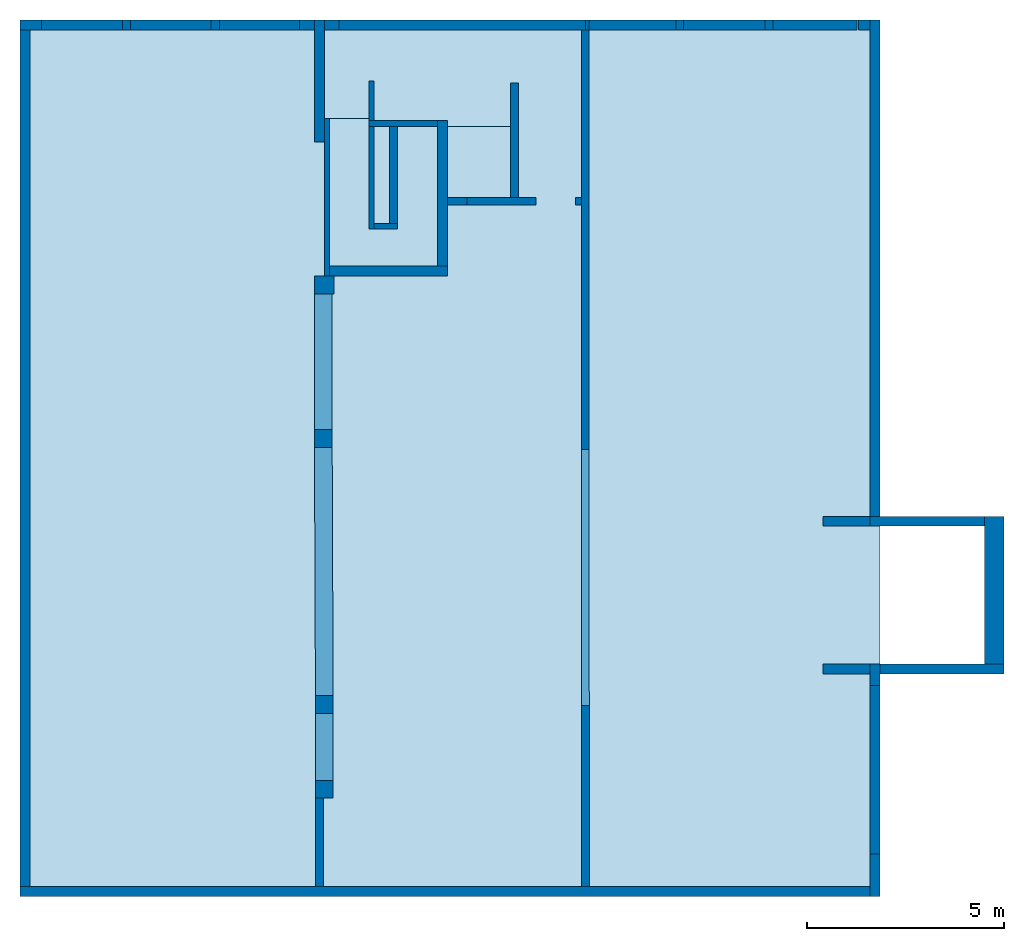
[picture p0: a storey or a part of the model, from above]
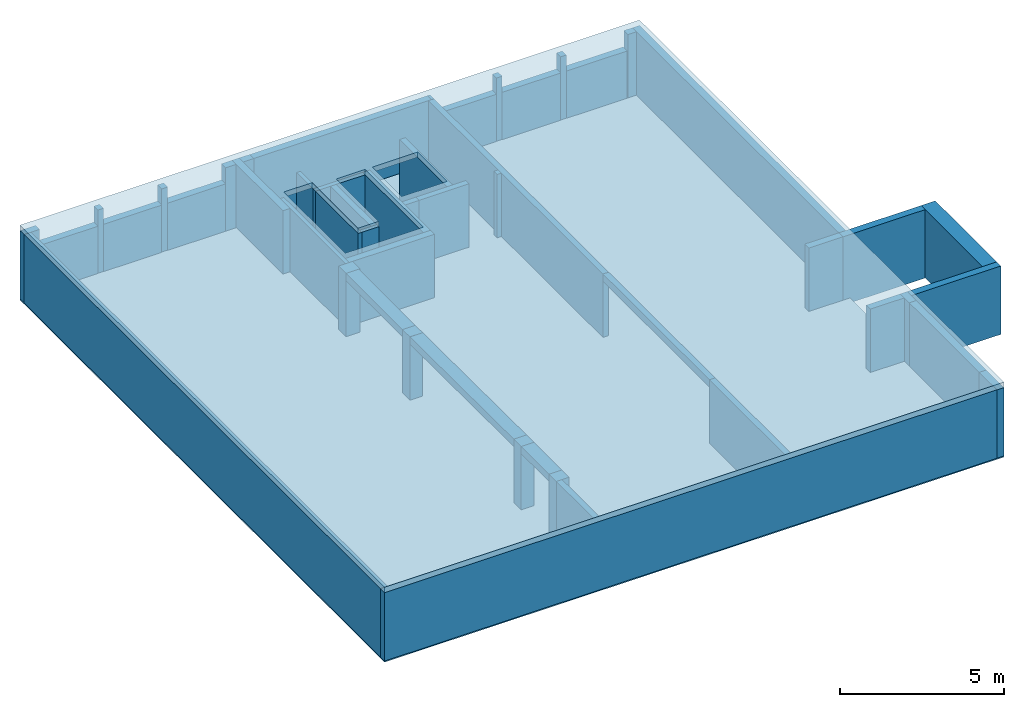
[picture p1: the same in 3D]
Properties of the parts of a building model (IFC2X3), part 1 of 2

# File
Description: ViewDefinition [CoordinationView_V2.0]
File name: C:\Users\steph\Desktop\Les Amaryllis complet pour Pcmo.ifc
Time: 2018-03-06T16:20:58
Author: Stéphane Hédouin
Organization: Nemetschek AG, Konrad-Zuse-Platz 1, 81829 Munich / Germany
Written by: EDMsix Version 2.0100.09 Sep 7 2016
Made in: Allplan 2018.0 16.11.2017 - 17:54:46

# IfcBuildingStorey (9)
In: Bâtiment
Name | Elevation (mm)
Sous-sol | -820
Rez-de-chaussée | 1760
1. Etage supérieur | 5290
2. Etage supérieur | 8450
3. Etage supérieur | 11610
4. Etage supérieur | 14770
5. Etage supérieur | 17930
6. Etage supérieur | 21090
7. Etage supérieur | 24250

# IfcBeam (24)
Material: <Unnamed Material>
Allplan Attributes - Catégorie de transformation: Nouvelle construction; Unité: m³
Name | In | Id_élt_Allmétré | NOI_UUID
<Unnamed Element> | Sous-sol | 0016S-p0000000009 | 486eb78d-af97-4655-ac4d-8411c6632bff--9
<Unnamed Element> | Sous-sol | 0016S-p0000000042 | 486eb78d-af97-4655-ac4d-8411c6632bff--42
<Unnamed Element> | Sous-sol | 0016S-p0000000049 | 486eb78d-af97-4655-ac4d-8411c6632bff--49
<Unnamed Element> | Sous-sol | 0016S-p0000000056 | 486eb78d-af97-4655-ac4d-8411c6632bff--56
<Unnamed Element> | Rez-de-chaussée | 0021S-p0000000030 | c5724ceb-6a8d-472c-a120-23266ca61e00--30
<Unnamed Element> | Rez-de-chaussée | 0021S-p0000000070 | c5724ceb-6a8d-472c-a120-23266ca61e00--70
<Unnamed Element> | Rez-de-chaussée | 0021S-p0000000063 | c5724ceb-6a8d-472c-a120-23266ca61e00--63
<Unnamed Element> | Rez-de-chaussée | 0021S-p0000000087 | c5724ceb-6a8d-472c-a120-23266ca61e00--87
<Unnamed Element> | Rez-de-chaussée | 0026S-p0000000118 | 649dd6d8-949c-4e9c-8996-63496c3fb143--118
<Unnamed Element> | Rez-de-chaussée | 0026S-p0000000126 | 649dd6d8-949c-4e9c-8996-63496c3fb143--126
<Unnamed Element> | Rez-de-chaussée | 0026S-p0000000246 | 649dd6d8-949c-4e9c-8996-63496c3fb143--246
<Unnamed Element> | 1. Etage supérieur | 0036S-p0000000018 | 9f9f1d74-6787-4617-af09-cd7453f099d3--18
<Unnamed Element> | 1. Etage supérieur | 0036S-p0000000057 | 9f9f1d74-6787-4617-af09-cd7453f099d3--57
<Unnamed Element> | 2. Etage supérieur | 0045S-p0000000002 | bfc77528-25da-4b58-ab56-61afc3e5380b--2
<Unnamed Element> | 2. Etage supérieur | 0045S-p0000000018 | bfc77528-25da-4b58-ab56-61afc3e5380b--18
<Unnamed Element> | 3. Etage supérieur | 0055S-p0000000017 | d36cbc1e-5176-4e0f-bb4e-4c807371ef2f--17
<Unnamed Element> | 3. Etage supérieur | 0055S-p0000000029 | d36cbc1e-5176-4e0f-bb4e-4c807371ef2f--29
<Unnamed Element> | 4. Etage supérieur | 0065S-p0000000069 | abeea69c-95b9-4fff-9f77-7789fcc0d115--69
<Unnamed Element> | 4. Etage supérieur | 0065S-p0000000017 | abeea69c-95b9-4fff-9f77-7789fcc0d115--17
<Unnamed Element> | 5. Etage supérieur | 0074S-p0000000016 | 6cb43bc7-a598-477d-aef1-ae12541f4cc3--16
<Unnamed Element> | 6. Etage supérieur | 0084S-p0000000007 | f4a9a238-371e-4109-9c43-8067f733ca4d--7
<Unnamed Element> | 6. Etage supérieur | 0084S-p0000000014 | f4a9a238-371e-4109-9c43-8067f733ca4d--14
<Unnamed Element> | 6. Etage supérieur | 0084S-p0000000070 | f4a9a238-371e-4109-9c43-8067f733ca4d--70
<Unnamed Element> | 6. Etage supérieur | 0084S-p0000000077 | f4a9a238-371e-4109-9c43-8067f733ca4d--77

# IfcColumn (21)
Material: <Unnamed Material>
Allplan Attributes - Catégorie de transformation: Nouvelle construction; Unité: m
Name | In | Id_élt_Allmétré | NOI_UUID
<Unnamed Element> | Sous-sol | 0013Pot0000000101 | f5a8dc2b-c76c-4dda-bb0b-31f6e3ff0e0c--101
<Unnamed Element> | Sous-sol | 0013Pot0000000109 | f5a8dc2b-c76c-4dda-bb0b-31f6e3ff0e0c--109
<Unnamed Element> | Sous-sol | 0013Pot0000000036 | f5a8dc2b-c76c-4dda-bb0b-31f6e3ff0e0c--36
<Unnamed Element> | Sous-sol | 0013Pot0000000044 | f5a8dc2b-c76c-4dda-bb0b-31f6e3ff0e0c--44
<Unnamed Element> | Sous-sol | 0013Pot0000000169 | f5a8dc2b-c76c-4dda-bb0b-31f6e3ff0e0c--169
<Unnamed Element> | Sous-sol | 0013Pot0000000177 | f5a8dc2b-c76c-4dda-bb0b-31f6e3ff0e0c--177
<Unnamed Element> | Sous-sol | 0013Pot0000000463 | f5a8dc2b-c76c-4dda-bb0b-31f6e3ff0e0c--463
<Unnamed Element> | Sous-sol | 0013Pot0000000455 | f5a8dc2b-c76c-4dda-bb0b-31f6e3ff0e0c--455
<Unnamed Element> | Rez-de-chaussée | 0022Pot0000000309 | 0e2b27f9-10d3-4386-be4d-cd432914257b--309
<Unnamed Element> | Rez-de-chaussée | 0023Pot0000000124 | 0033ac79-3276-4870-90e0-ad52ccc84e25--124
<Unnamed Element> | Rez-de-chaussée | 0023Pot0000000121 | 0033ac79-3276-4870-90e0-ad52ccc84e25--121
<Unnamed Element> | Rez-de-chaussée | 0023Pot0000000118 | 0033ac79-3276-4870-90e0-ad52ccc84e25--118
<Unnamed Element> | Rez-de-chaussée | 0023Pot0000000115 | 0033ac79-3276-4870-90e0-ad52ccc84e25--115
<Unnamed Element> | Rez-de-chaussée | 0023Pot0000000112 | 0033ac79-3276-4870-90e0-ad52ccc84e25--112
<Unnamed Element> | Rez-de-chaussée | 0023Pot0000000109 | 0033ac79-3276-4870-90e0-ad52ccc84e25--109
<Unnamed Element> | Rez-de-chaussée | 0023Pot0000000106 | 0033ac79-3276-4870-90e0-ad52ccc84e25--106
<Unnamed Element> | Rez-de-chaussée | 0023Pot0000000103 | 0033ac79-3276-4870-90e0-ad52ccc84e25--103
<Unnamed Element> | Rez-de-chaussée | 0023Pot0000000100 | 0033ac79-3276-4870-90e0-ad52ccc84e25--100
<Unnamed Element> | Rez-de-chaussée | 0023Pot0000000097 | 0033ac79-3276-4870-90e0-ad52ccc84e25--97
<Unnamed Element> | Rez-de-chaussée | 0023Pot0000000091 | 0033ac79-3276-4870-90e0-ad52ccc84e25--91
<Unnamed Element> | Rez-de-chaussée | 0023Pot0000000094 | 0033ac79-3276-4870-90e0-ad52ccc84e25--94

# IfcOpeningElement: Opening (179)
Allplan Attributes - Object Layer Attributes #1, Catégorie de transformation: Nouvelle construction; Object Layer Attributes #1, Unité: m²
Name | In | Object Layer Attributes #1, Id_élt_Allmétré | Object Layer Attributes #1, NOI_UUID | Object Layer Attributes #1, Métier
Trémie dans dalle | Sous-sol | 0014TrD0000000013 | 20334fe0-4999-4aaf-8585-79f5e6d3d731--13
Trémie dans dalle | Sous-sol | 0014TrD0000000025 | 20334fe0-4999-4aaf-8585-79f5e6d3d731--25
Trémie dans dalle | Rez-de-chaussée | 0027TrD0000000023 | d315fca0-df44-48a9-a052-42f8cd2f5afa--23
Trémie dans dalle | Rez-de-chaussée | 0027TrD0000000180 | d315fca0-df44-48a9-a052-42f8cd2f5afa--180
Baie de porte | 1. Etage supérieur | 0032Por0000004570 | 6a1e8f65-a2b8-4168-b325-3206246c0164--4570 | Béton et béton armé
Baie de fenêtre | 1. Etage supérieur | 0032Fen0000004470 | 6a1e8f65-a2b8-4168-b325-3206246c0164--4470 | Béton et béton armé
Baie de fenêtre | 1. Etage supérieur | 0032Fen0000004484 | 6a1e8f65-a2b8-4168-b325-3206246c0164--4484 | Béton et béton armé
Baie de fenêtre | 1. Etage supérieur | 0032Fen0000004417 | 6a1e8f65-a2b8-4168-b325-3206246c0164--4417 | Béton et béton armé
Baie de fenêtre | 1. Etage supérieur | 0032Fen0000004432 | 6a1e8f65-a2b8-4168-b325-3206246c0164--4432 | Béton et béton armé
Baie de fenêtre | 1. Etage supérieur | 0032Fen0000004445 | 6a1e8f65-a2b8-4168-b325-3206246c0164--4445 | Béton et béton armé
Baie de fenêtre | 1. Etage supérieur | 0032Fen0000004458 | 6a1e8f65-a2b8-4168-b325-3206246c0164--4458 | Béton et béton armé
Baie de fenêtre | 1. Etage supérieur | 0032Fen0000004272 | 6a1e8f65-a2b8-4168-b325-3206246c0164--4272 | Béton et béton armé
Baie de fenêtre | 1. Etage supérieur | 0032Fen0000004288 | 6a1e8f65-a2b8-4168-b325-3206246c0164--4288 | Béton et béton armé
Baie de fenêtre | 1. Etage supérieur | 0032Fen0000004332 | 6a1e8f65-a2b8-4168-b325-3206246c0164--4332 | Béton et béton armé
Baie de porte | 1. Etage supérieur | 0032Por0000004666 | 6a1e8f65-a2b8-4168-b325-3206246c0164--4666 | Béton et béton armé
Baie de fenêtre | 1. Etage supérieur | 0032Fen0000004525 | 6a1e8f65-a2b8-4168-b325-3206246c0164--4525 | Béton et béton armé
Baie de fenêtre | 1. Etage supérieur | 0032Fen0000004583 | 6a1e8f65-a2b8-4168-b325-3206246c0164--4583 | Béton et béton armé
Baie de fenêtre | 1. Etage supérieur | 0032Fen0000004593 | 6a1e8f65-a2b8-4168-b325-3206246c0164--4593 | Béton et béton armé
Baie de fenêtre | 1. Etage supérieur | 0032Fen0000004535 | 6a1e8f65-a2b8-4168-b325-3206246c0164--4535 | Béton et béton armé
Baie de fenêtre | 1. Etage supérieur | 0032Fen0000003807 | 6a1e8f65-a2b8-4168-b325-3206246c0164--3807 | Béton et béton armé
Baie de fenêtre | 1. Etage supérieur | 0032Fen0000004259 | 6a1e8f65-a2b8-4168-b325-3206246c0164--4259 | Béton et béton armé
Baie de fenêtre | 1. Etage supérieur | 0032Fen0000004400 | 6a1e8f65-a2b8-4168-b325-3206246c0164--4400 | Béton et béton armé
Baie de fenêtre | 1. Etage supérieur | 0032Fen0000004386 | 6a1e8f65-a2b8-4168-b325-3206246c0164--4386 | Béton et béton armé
Baie de fenêtre | 1. Etage supérieur | 0032Fen0000004360 | 6a1e8f65-a2b8-4168-b325-3206246c0164--4360 | Béton et béton armé
Baie de fenêtre | 1. Etage supérieur | 0032Fen0000004346 | 6a1e8f65-a2b8-4168-b325-3206246c0164--4346 | Béton et béton armé
Trémie dans dalle | 1. Etage supérieur | 0034TrD0000000056 | ebf78192-9004-4931-9720-7fce9c6b5ec9--56
Trémie dans dalle | 1. Etage supérieur | 0034TrD0000000061 | ebf78192-9004-4931-9720-7fce9c6b5ec9--61
Baie de fenêtre | 2. Etage supérieur | 0042Fen0000000908 | 90a796d3-f0ad-4bd1-a568-830c8568f6ce--908 | Menuiserie
Baie de fenêtre | 2. Etage supérieur | 0042Fen0000000878 | 90a796d3-f0ad-4bd1-a568-830c8568f6ce--878 | Menuiserie
Baie de fenêtre | 2. Etage supérieur | 0042Fen0000000868 | 90a796d3-f0ad-4bd1-a568-830c8568f6ce--868 | Menuiserie
Baie de fenêtre | 2. Etage supérieur | 0042Fen0000000784 | 90a796d3-f0ad-4bd1-a568-830c8568f6ce--784 | Menuiserie
Baie de fenêtre | 2. Etage supérieur | 0042Fen0000000794 | 90a796d3-f0ad-4bd1-a568-830c8568f6ce--794 | Menuiserie
Baie de fenêtre | 2. Etage supérieur | 0042Fen0000000772 | 90a796d3-f0ad-4bd1-a568-830c8568f6ce--772 | Menuiserie
Baie de fenêtre | 2. Etage supérieur | 0042Fen0000000748 | 90a796d3-f0ad-4bd1-a568-830c8568f6ce--748 | Menuiserie
Baie de fenêtre | 2. Etage supérieur | 0042Fen0000000760 | 90a796d3-f0ad-4bd1-a568-830c8568f6ce--760 | Menuiserie
Baie de fenêtre | 2. Etage supérieur | 0042Fen0000000706 | 90a796d3-f0ad-4bd1-a568-830c8568f6ce--706 | Menuiserie
Porte-fenêtre | 2. Etage supérieur | 0042PoF0000001016 | 90a796d3-f0ad-4bd1-a568-830c8568f6ce--1016 | Menuiserie
Baie de fenêtre | 2. Etage supérieur | 0042Fen0000000918 | 90a796d3-f0ad-4bd1-a568-830c8568f6ce--918 | Menuiserie
Baie de fenêtre | 2. Etage supérieur | 0042Fen0000000858 | 90a796d3-f0ad-4bd1-a568-830c8568f6ce--858 | Menuiserie
Baie de fenêtre | 2. Etage supérieur | 0042Fen0000000848 | 90a796d3-f0ad-4bd1-a568-830c8568f6ce--848 | Menuiserie
Baie de fenêtre | 2. Etage supérieur | 0042Fen0000000898 | 90a796d3-f0ad-4bd1-a568-830c8568f6ce--898 | Menuiserie
Baie de fenêtre | 2. Etage supérieur | 0042Fen0000000928 | 90a796d3-f0ad-4bd1-a568-830c8568f6ce--928 | Menuiserie
Baie de fenêtre | 2. Etage supérieur | 0042Fen0000000938 | 90a796d3-f0ad-4bd1-a568-830c8568f6ce--938 | Menuiserie
Baie de fenêtre | 2. Etage supérieur | 0042Fen0000000888 | 90a796d3-f0ad-4bd1-a568-830c8568f6ce--888 | Menuiserie
Baie de fenêtre | 2. Etage supérieur | 0042Fen0000000838 | 90a796d3-f0ad-4bd1-a568-830c8568f6ce--838 | Menuiserie
Baie de fenêtre | 2. Etage supérieur | 0042Fen0000000828 | 90a796d3-f0ad-4bd1-a568-830c8568f6ce--828 | Menuiserie
Baie de fenêtre | 2. Etage supérieur | 0042Fen0000000818 | 90a796d3-f0ad-4bd1-a568-830c8568f6ce--818 | Menuiserie
Baie de fenêtre | 2. Etage supérieur | 0042Fen0000000808 | 90a796d3-f0ad-4bd1-a568-830c8568f6ce--808 | Menuiserie
Porte-fenêtre | 2. Etage supérieur | 0042PoF0000002495 | 90a796d3-f0ad-4bd1-a568-830c8568f6ce--2495 | Menuiserie
Baie de fenêtre | 2. Etage supérieur | 0042Fen0000001087 | 90a796d3-f0ad-4bd1-a568-830c8568f6ce--1087 | Menuiserie
Baie de fenêtre | 2. Etage supérieur | 0042Fen0000001131 | 90a796d3-f0ad-4bd1-a568-830c8568f6ce--1131 | Menuiserie
Baie de fenêtre | 2. Etage supérieur | 0042Fen0000001121 | 90a796d3-f0ad-4bd1-a568-830c8568f6ce--1121 | Menuiserie
Baie de fenêtre | 2. Etage supérieur | 0042Fen0000002478 | 90a796d3-f0ad-4bd1-a568-830c8568f6ce--2478 | Menuiserie
Trémie dans dalle | 2. Etage supérieur | 0043TrD0000000213 | 678bda4c-4d8f-426f-a236-f3a8bbcb65b3--213
Trémie dans dalle | 2. Etage supérieur | 0043TrD0000000220 | 678bda4c-4d8f-426f-a236-f3a8bbcb65b3--220
Trémie dans dalle | 2. Etage supérieur | 0043TrD0000000225 | 678bda4c-4d8f-426f-a236-f3a8bbcb65b3--225
Baie de fenêtre | 3. Etage supérieur | 0052Fen0000000426 | 435ab560-3884-4131-b1cc-7aba0e0d0a30--426 | Menuiserie
Baie de fenêtre | 3. Etage supérieur | 0052Fen0000000436 | 435ab560-3884-4131-b1cc-7aba0e0d0a30--436 | Menuiserie
Porte-fenêtre | 3. Etage supérieur | 0052PoF0000000588 | 435ab560-3884-4131-b1cc-7aba0e0d0a30--588 | Menuiserie
Baie de fenêtre | 3. Etage supérieur | 0052Fen0000000710 | 435ab560-3884-4131-b1cc-7aba0e0d0a30--710 | Menuiserie
Baie de fenêtre | 3. Etage supérieur | 0052Fen0000000690 | 435ab560-3884-4131-b1cc-7aba0e0d0a30--690 | Menuiserie
Baie de fenêtre | 3. Etage supérieur | 0052Fen0000000700 | 435ab560-3884-4131-b1cc-7aba0e0d0a30--700 | Menuiserie
Baie de fenêtre | 3. Etage supérieur | 0052Fen0000000720 | 435ab560-3884-4131-b1cc-7aba0e0d0a30--720 | Menuiserie
Porte-fenêtre | 3. Etage supérieur | 0052PoF0000000577 | 435ab560-3884-4131-b1cc-7aba0e0d0a30--577 | Menuiserie
Baie de fenêtre | 3. Etage supérieur | 0052Fen0000000416 | 435ab560-3884-4131-b1cc-7aba0e0d0a30--416 | Menuiserie
Baie de fenêtre | 3. Etage supérieur | 0052Fen0000000372 | 435ab560-3884-4131-b1cc-7aba0e0d0a30--372 | Menuiserie
Baie de fenêtre | 3. Etage supérieur | 0052Fen0000000402 | 435ab560-3884-4131-b1cc-7aba0e0d0a30--402 | Menuiserie
Baie de fenêtre | 3. Etage supérieur | 0052Fen0000000526 | 435ab560-3884-4131-b1cc-7aba0e0d0a30--526 | Menuiserie
Baie de fenêtre | 3. Etage supérieur | 0052Fen0000000516 | 435ab560-3884-4131-b1cc-7aba0e0d0a30--516 | Menuiserie
Baie de fenêtre | 3. Etage supérieur | 0052Fen0000000506 | 435ab560-3884-4131-b1cc-7aba0e0d0a30--506 | Menuiserie
Baie de fenêtre | 3. Etage supérieur | 0052Fen0000000496 | 435ab560-3884-4131-b1cc-7aba0e0d0a30--496 | Menuiserie
Baie de fenêtre | 3. Etage supérieur | 0052Fen0000000392 | 435ab560-3884-4131-b1cc-7aba0e0d0a30--392 | Menuiserie
Baie de fenêtre | 3. Etage supérieur | 0052Fen0000000486 | 435ab560-3884-4131-b1cc-7aba0e0d0a30--486 | Menuiserie
Baie de fenêtre | 3. Etage supérieur | 0052Fen0000000476 | 435ab560-3884-4131-b1cc-7aba0e0d0a30--476 | Menuiserie
Baie de fenêtre | 3. Etage supérieur | 0052Fen0000000466 | 435ab560-3884-4131-b1cc-7aba0e0d0a30--466 | Menuiserie
Baie de fenêtre | 3. Etage supérieur | 0052Fen0000000362 | 435ab560-3884-4131-b1cc-7aba0e0d0a30--362 | Menuiserie
Baie de fenêtre | 3. Etage supérieur | 0052Fen0000000352 | 435ab560-3884-4131-b1cc-7aba0e0d0a30--352 | Menuiserie
Baie de fenêtre | 3. Etage supérieur | 0052Fen0000000456 | 435ab560-3884-4131-b1cc-7aba0e0d0a30--456 | Menuiserie
Baie de fenêtre | 3. Etage supérieur | 0052Fen0000000446 | 435ab560-3884-4131-b1cc-7aba0e0d0a30--446 | Menuiserie
Baie de fenêtre | 3. Etage supérieur | 0052Fen0000000382 | 435ab560-3884-4131-b1cc-7aba0e0d0a30--382 | Menuiserie
Baie de fenêtre | 3. Etage supérieur | 0052Fen0000000340 | 435ab560-3884-4131-b1cc-7aba0e0d0a30--340 | Menuiserie
Porte-fenêtre | 3. Etage supérieur | 0052PoF0000000622 | 435ab560-3884-4131-b1cc-7aba0e0d0a30--622 | Menuiserie
Porte-fenêtre | 3. Etage supérieur | 0052PoF0000000633 | 435ab560-3884-4131-b1cc-7aba0e0d0a30--633 | Menuiserie
Porte-fenêtre | 3. Etage supérieur | 0052PoF0000000611 | 435ab560-3884-4131-b1cc-7aba0e0d0a30--611 | Menuiserie
Porte-fenêtre | 3. Etage supérieur | 0052PoF0000000679 | 435ab560-3884-4131-b1cc-7aba0e0d0a30--679 | Menuiserie
Porte-fenêtre | 3. Etage supérieur | 0052PoF0000000668 | 435ab560-3884-4131-b1cc-7aba0e0d0a30--668 | Menuiserie
Trémie dans dalle | 3. Etage supérieur | 0053TrD0000000277 | 48b77cce-8fe0-481c-bd89-f567615fd88a--277
Trémie dans dalle | 3. Etage supérieur | 0053TrD0000000282 | 48b77cce-8fe0-481c-bd89-f567615fd88a--282
Trémie dans dalle | 3. Etage supérieur | 0053TrD0000000287 | 48b77cce-8fe0-481c-bd89-f567615fd88a--287
Porte-fenêtre | 4. Etage supérieur | 0062PoF0000001083 | 347db150-1122-4b3f-bc21-631404b16890--1083 | Menuiserie
Porte-fenêtre | 4. Etage supérieur | 0062PoF0000000532 | 347db150-1122-4b3f-bc21-631404b16890--532 | Menuiserie
Porte-fenêtre | 4. Etage supérieur | 0062PoF0000001070 | 347db150-1122-4b3f-bc21-631404b16890--1070 | Menuiserie
Porte-fenêtre | 4. Etage supérieur | 0062PoF0000000486 | 347db150-1122-4b3f-bc21-631404b16890--486 | Menuiserie
Porte-fenêtre | 4. Etage supérieur | 0062PoF0000000543 | 347db150-1122-4b3f-bc21-631404b16890--543 | Menuiserie
Baie de fenêtre | 4. Etage supérieur | 0062Fen0000001057 | 347db150-1122-4b3f-bc21-631404b16890--1057 | Menuiserie
Porte-fenêtre | 4. Etage supérieur | 0062PoF0000000470 | 347db150-1122-4b3f-bc21-631404b16890--470 | Menuiserie
Baie de fenêtre | 4. Etage supérieur | 0062Fen0000000554 | 347db150-1122-4b3f-bc21-631404b16890--554 | Menuiserie
Baie de fenêtre | 4. Etage supérieur | 0062Fen0000000560 | 347db150-1122-4b3f-bc21-631404b16890--560 | Menuiserie
Baie de fenêtre | 4. Etage supérieur | 0062Fen0000000572 | 347db150-1122-4b3f-bc21-631404b16890--572 | Menuiserie
Baie de fenêtre | 4. Etage supérieur | 0062Fen0000000566 | 347db150-1122-4b3f-bc21-631404b16890--566 | Menuiserie
Porte-fenêtre | 4. Etage supérieur | 0062PoF0000000459 | 347db150-1122-4b3f-bc21-631404b16890--459 | Menuiserie
Baie de fenêtre | 4. Etage supérieur | 0062Fen0000001041 | 347db150-1122-4b3f-bc21-631404b16890--1041 | Menuiserie
Baie de fenêtre | 4. Etage supérieur | 0062Fen0000001029 | 347db150-1122-4b3f-bc21-631404b16890--1029 | Menuiserie
Baie de fenêtre | 4. Etage supérieur | 0062Fen0000001017 | 347db150-1122-4b3f-bc21-631404b16890--1017 | Menuiserie
Baie de fenêtre | 4. Etage supérieur | 0062Fen0000000995 | 347db150-1122-4b3f-bc21-631404b16890--995 | Menuiserie
Baie de fenêtre | 4. Etage supérieur | 0062Fen0000000983 | 347db150-1122-4b3f-bc21-631404b16890--983 | Menuiserie
Baie de fenêtre | 4. Etage supérieur | 0062Fen0000000971 | 347db150-1122-4b3f-bc21-631404b16890--971 | Menuiserie
Baie de fenêtre | 4. Etage supérieur | 0062Fen0000000959 | 347db150-1122-4b3f-bc21-631404b16890--959 | Menuiserie
Baie de fenêtre | 4. Etage supérieur | 0062Fen0000000947 | 347db150-1122-4b3f-bc21-631404b16890--947 | Menuiserie
Baie de fenêtre | 4. Etage supérieur | 0062Fen0000000925 | 347db150-1122-4b3f-bc21-631404b16890--925 | Menuiserie
Baie de fenêtre | 4. Etage supérieur | 0062Fen0000000913 | 347db150-1122-4b3f-bc21-631404b16890--913 | Menuiserie
Baie de fenêtre | 4. Etage supérieur | 0062Fen0000000901 | 347db150-1122-4b3f-bc21-631404b16890--901 | Menuiserie
Baie de fenêtre | 4. Etage supérieur | 0062Fen0000000889 | 347db150-1122-4b3f-bc21-631404b16890--889 | Menuiserie
Baie de fenêtre | 4. Etage supérieur | 0062Fen0000000877 | 347db150-1122-4b3f-bc21-631404b16890--877 | Menuiserie
Porte-fenêtre | 4. Etage supérieur | 0062PoF0000000497 | 347db150-1122-4b3f-bc21-631404b16890--497 | Menuiserie
Porte-fenêtre | 4. Etage supérieur | 0062PoF0000000504 | 347db150-1122-4b3f-bc21-631404b16890--504 | Menuiserie
Baie de fenêtre | 4. Etage supérieur | 0062Fen0000000855 | 347db150-1122-4b3f-bc21-631404b16890--855 | Menuiserie
Baie de fenêtre | 4. Etage supérieur | 0062Fen0000000842 | 347db150-1122-4b3f-bc21-631404b16890--842 | Menuiserie
Baie de fenêtre | 4. Etage supérieur | 0062Fen0000000798 | 347db150-1122-4b3f-bc21-631404b16890--798 | Menuiserie
Trémie dans dalle | 4. Etage supérieur | 0063TrD0000000021 | 91ba3f86-ed78-430b-84a1-b3a13398379c--21
Trémie dans dalle | 4. Etage supérieur | 0063TrD0000000026 | 91ba3f86-ed78-430b-84a1-b3a13398379c--26
Trémie dans dalle | 4. Etage supérieur | 0063TrD0000000016 | 91ba3f86-ed78-430b-84a1-b3a13398379c--16
Porte-fenêtre | 5. Etage supérieur | 0071PoF0000001617 | ef38cf39-5122-4ad7-8e20-12f51fd6f56f--1617 | Menuiserie
Porte-fenêtre | 5. Etage supérieur | 0071PoF0000001629 | ef38cf39-5122-4ad7-8e20-12f51fd6f56f--1629 | Menuiserie
Baie de fenêtre | 5. Etage supérieur | 0071Fen0000001931 | ef38cf39-5122-4ad7-8e20-12f51fd6f56f--1931 | Menuiserie
Baie de fenêtre | 5. Etage supérieur | 0071Fen0000001943 | ef38cf39-5122-4ad7-8e20-12f51fd6f56f--1943 | Menuiserie
Baie de fenêtre | 5. Etage supérieur | 0071Fen0000002153 | ef38cf39-5122-4ad7-8e20-12f51fd6f56f--2153 | Menuiserie
Baie de fenêtre | 5. Etage supérieur | 0071Fen0000002141 | ef38cf39-5122-4ad7-8e20-12f51fd6f56f--2141 | Menuiserie
Porte-fenêtre | 5. Etage supérieur | 0071PoF0000001467 | ef38cf39-5122-4ad7-8e20-12f51fd6f56f--1467 | Menuiserie
Baie de fenêtre | 5. Etage supérieur | 0071Fen0000001504 | ef38cf39-5122-4ad7-8e20-12f51fd6f56f--1504 | Menuiserie
Baie de fenêtre | 5. Etage supérieur | 0071Fen0000001500 | ef38cf39-5122-4ad7-8e20-12f51fd6f56f--1500 | Menuiserie
Baie de fenêtre | 5. Etage supérieur | 0071Fen0000001498 | ef38cf39-5122-4ad7-8e20-12f51fd6f56f--1498 | Menuiserie
Baie de fenêtre | 5. Etage supérieur | 0071Fen0000001502 | ef38cf39-5122-4ad7-8e20-12f51fd6f56f--1502 | Menuiserie
Porte-fenêtre | 5. Etage supérieur | 0071PoF0000001533 | ef38cf39-5122-4ad7-8e20-12f51fd6f56f--1533 | Menuiserie
Baie de fenêtre | 5. Etage supérieur | 0071Fen0000002117 | ef38cf39-5122-4ad7-8e20-12f51fd6f56f--2117 | Menuiserie
Baie de fenêtre | 5. Etage supérieur | 0071Fen0000002129 | ef38cf39-5122-4ad7-8e20-12f51fd6f56f--2129 | Menuiserie
Baie de fenêtre | 5. Etage supérieur | 0071Fen0000002079 | ef38cf39-5122-4ad7-8e20-12f51fd6f56f--2079 | Menuiserie
Baie de fenêtre | 5. Etage supérieur | 0071Fen0000002043 | ef38cf39-5122-4ad7-8e20-12f51fd6f56f--2043 | Menuiserie
Baie de fenêtre | 5. Etage supérieur | 0071Fen0000002055 | ef38cf39-5122-4ad7-8e20-12f51fd6f56f--2055 | Menuiserie
Baie de fenêtre | 5. Etage supérieur | 0071Fen0000002067 | ef38cf39-5122-4ad7-8e20-12f51fd6f56f--2067 | Menuiserie
Baie de fenêtre | 5. Etage supérieur | 0071Fen0000002089 | ef38cf39-5122-4ad7-8e20-12f51fd6f56f--2089 | Menuiserie
Baie de fenêtre | 5. Etage supérieur | 0071Fen0000002105 | ef38cf39-5122-4ad7-8e20-12f51fd6f56f--2105 | Menuiserie
Porte-fenêtre | 5. Etage supérieur | 0071PoF0000001555 | ef38cf39-5122-4ad7-8e20-12f51fd6f56f--1555 | Menuiserie
Porte-fenêtre | 5. Etage supérieur | 0071PoF0000001568 | ef38cf39-5122-4ad7-8e20-12f51fd6f56f--1568 | Menuiserie
Porte-fenêtre | 5. Etage supérieur | 0071PoF0000001566 | ef38cf39-5122-4ad7-8e20-12f51fd6f56f--1566 | Menuiserie
Porte-fenêtre | 5. Etage supérieur | 0071PoF0000001581 | ef38cf39-5122-4ad7-8e20-12f51fd6f56f--1581 | Menuiserie
Baie de fenêtre | 5. Etage supérieur | 0071Fen0000002031 | ef38cf39-5122-4ad7-8e20-12f51fd6f56f--2031 | Menuiserie
Baie de fenêtre | 5. Etage supérieur | 0071Fen0000002019 | ef38cf39-5122-4ad7-8e20-12f51fd6f56f--2019 | Menuiserie
Baie de fenêtre | 5. Etage supérieur | 0071Fen0000002007 | ef38cf39-5122-4ad7-8e20-12f51fd6f56f--2007 | Menuiserie
Baie de fenêtre | 5. Etage supérieur | 0071Fen0000001995 | ef38cf39-5122-4ad7-8e20-12f51fd6f56f--1995 | Menuiserie
Baie de fenêtre | 5. Etage supérieur | 0071Fen0000001983 | ef38cf39-5122-4ad7-8e20-12f51fd6f56f--1983 | Menuiserie
Trémie dans dalle | 5. Etage supérieur | 0072TrD0000000020 | dce49d39-f4d7-4afb-90a5-12dc6dbe4ed2--20
Trémie dans dalle | 5. Etage supérieur | 0072TrD0000000025 | dce49d39-f4d7-4afb-90a5-12dc6dbe4ed2--25
Baie de fenêtre | 6. Etage supérieur | 0082Fen0000000678 | 5473e48a-e790-4312-ac25-e6982c2e7877--678 | Béton et béton armé
Baie de fenêtre | 6. Etage supérieur | 0082Fen0000000692 | 5473e48a-e790-4312-ac25-e6982c2e7877--692 | Béton et béton armé
Baie de fenêtre | 6. Etage supérieur | 0082Fen0000000704 | 5473e48a-e790-4312-ac25-e6982c2e7877--704 | Béton et béton armé
Baie de fenêtre | 6. Etage supérieur | 0082Fen0000000728 | 5473e48a-e790-4312-ac25-e6982c2e7877--728 | Béton et béton armé
Baie de fenêtre | 6. Etage supérieur | 0082Fen0000000750 | 5473e48a-e790-4312-ac25-e6982c2e7877--750 | Béton et béton armé
Baie de fenêtre | 6. Etage supérieur | 0082Fen0000000774 | 5473e48a-e790-4312-ac25-e6982c2e7877--774 | Béton et béton armé
Baie de fenêtre | 6. Etage supérieur | 0082Fen0000000786 | 5473e48a-e790-4312-ac25-e6982c2e7877--786 | Béton et béton armé
Baie de fenêtre | 6. Etage supérieur | 0082Fen0000000798 | 5473e48a-e790-4312-ac25-e6982c2e7877--798 | Béton et béton armé
Baie de fenêtre | 6. Etage supérieur | 0082Fen0000000810 | 5473e48a-e790-4312-ac25-e6982c2e7877--810 | Béton et béton armé
Baie de porte | 6. Etage supérieur | 0082Por0000001034 | 5473e48a-e790-4312-ac25-e6982c2e7877--1034 | Béton et béton armé
Baie de fenêtre | 6. Etage supérieur | 0082Fen0000000762 | 5473e48a-e790-4312-ac25-e6982c2e7877--762 | Béton et béton armé
Baie de fenêtre | 6. Etage supérieur | 0082Fen0000000557 | 5473e48a-e790-4312-ac25-e6982c2e7877--557 | Béton et béton armé
Baie de fenêtre | 6. Etage supérieur | 0082Fen0000000569 | 5473e48a-e790-4312-ac25-e6982c2e7877--569 | Béton et béton armé
Baie de fenêtre | 6. Etage supérieur | 0082Fen0000000581 | 5473e48a-e790-4312-ac25-e6982c2e7877--581 | Béton et béton armé
Baie de fenêtre | 6. Etage supérieur | 0082Fen0000000593 | 5473e48a-e790-4312-ac25-e6982c2e7877--593 | Béton et béton armé
Baie de fenêtre | 6. Etage supérieur | 0082Fen0000000605 | 5473e48a-e790-4312-ac25-e6982c2e7877--605 | Béton et béton armé
Porte-fenêtre | 6. Etage supérieur | 0082PoF0000000849 | 5473e48a-e790-4312-ac25-e6982c2e7877--849 | Béton et béton armé
Porte-fenêtre | 6. Etage supérieur | 0082PoF0000000881 | 5473e48a-e790-4312-ac25-e6982c2e7877--881 | Béton et béton armé
Baie de fenêtre | 6. Etage supérieur | 0082Fen0000000618 | 5473e48a-e790-4312-ac25-e6982c2e7877--618 | Béton et béton armé
Baie de fenêtre | 6. Etage supérieur | 0082Fen0000000630 | 5473e48a-e790-4312-ac25-e6982c2e7877--630 | Béton et béton armé
Baie de fenêtre | 6. Etage supérieur | 0082Fen0000000642 | 5473e48a-e790-4312-ac25-e6982c2e7877--642 | Béton et béton armé
Baie de fenêtre | 6. Etage supérieur | 0082Fen0000000654 | 5473e48a-e790-4312-ac25-e6982c2e7877--654 | Béton et béton armé
Baie de fenêtre | 6. Etage supérieur | 0082Fen0000000666 | 5473e48a-e790-4312-ac25-e6982c2e7877--666 | Béton et béton armé
Baie de porte | 6. Etage supérieur | 0082Por0000001022 | 5473e48a-e790-4312-ac25-e6982c2e7877--1022 | Béton et béton armé
Trémie dans dalle | 6. Etage supérieur | 0083TrD0000000021 | f7d33bd0-1ac0-43b7-ade3-e2a972c2ffc9--21
Trémie dans dalle | 6. Etage supérieur | 0083TrD0000000026 | f7d33bd0-1ac0-43b7-ade3-e2a972c2ffc9--26

# IfcSlab (10)
PredefinedType: FLOOR
Allplan Attributes - Catégorie de transformation: Nouvelle construction; Unité: m²
Name | In | Material | Id_élt_Allmétré | NOI_UUID
<Unnamed Element> | Sous-sol | <Unnamed Material> 200 mm | 0014Dal0000000002 | 20334fe0-4999-4aaf-8585-79f5e6d3d731--2
<Unnamed Element> | Sous-sol | <Unnamed Material> 230 mm | 0018Dal0000000020 | c1ec093b-a0e2-4153-afd5-b799a6e003fa--20
<Unnamed Element> | Rez-de-chaussée | <Unnamed Material> 230 mm | 0027Dal0000000020 | d315fca0-df44-48a9-a052-42f8cd2f5afa--20
<Unnamed Element> | 1. Etage supérieur | <Unnamed Material> 230 mm | 0034Dal0000000053 | ebf78192-9004-4931-9720-7fce9c6b5ec9--53
<Unnamed Element> | 2. Etage supérieur | <Unnamed Material> 230 mm | 0043Dal0000000004 | 678bda4c-4d8f-426f-a236-f3a8bbcb65b3--4
<Unnamed Element> | 3. Etage supérieur | <Unnamed Material> 230 mm | 0053Dal0000000002 | 48b77cce-8fe0-481c-bd89-f567615fd88a--2
<Unnamed Element> | 4. Etage supérieur | <Unnamed Material> 230 mm | 0063Dal0000000002 | 91ba3f86-ed78-430b-84a1-b3a13398379c--2
<Unnamed Element> | 5. Etage supérieur | <Unnamed Material> 230 mm | 0072Dal0000000004 | dce49d39-f4d7-4afb-90a5-12dc6dbe4ed2--4
<Unnamed Element> | 6. Etage supérieur | <Unnamed Material> 230 mm | 0083Dal0000000002 | f7d33bd0-1ac0-43b7-ade3-e2a972c2ffc9--2
<Unnamed Element> | 7. Etage supérieur | <Unnamed Material> 200 mm | 0094Dal0000000003 | 8a5cfb47-16d0-4201-be59-6f41295b1b2b--3

# IfcStair, <Unnamed Element>
In: Rez-de-chaussée
Material: Escalier semi-tournant
Pset_StairCommon - NumberOfRiser: 16; RiserHeight: 246.25 mm; TreadLength: 300.83 mm; NumberOfTreads: 16
Allplan Attributes - Id_élt_Allmétré: 0026Esc0000000029; Unité: Qt; Matériau: Escalier semi-tournant; NOI_UUID: 649dd6d8-949c-4e9c-8996-63496c3fb143--29

# IfcWallStandardCase (211)
Allplan Attributes - Unité: m³; Object Layer Attributes #1, Catégorie de transformation: Nouvelle construction; Object Layer Attributes #1, Unité: m²
Name | In | Material | Id_élt_Allmétré | NOI_UUID | Object Layer Attributes #1, Id_élt_Allmétré | Object Layer Attributes #1, Métier | Object Layer Attributes #1, NOI_UUID
<Unnamed Element> | Sous-sol | <Unnamed Material> 250 mm | 0012HMu0000000156 | e7be45ff-019b-49bd-811e-5d1073b6d973--156 | 0012Mu_0000000157 | Béton et béton armé | e7be45ff-019b-49bd-811e-5d1073b6d973--157
<Unnamed Element> | Sous-sol | <Unnamed Material> 500 mm | 0012HMu0000000178 | e7be45ff-019b-49bd-811e-5d1073b6d973--178 | 0012Mu_0000000179 | Béton et béton armé | e7be45ff-019b-49bd-811e-5d1073b6d973--179
<Unnamed Element> | Sous-sol | <Unnamed Material> 250 mm | 0012HMu0000000199 | e7be45ff-019b-49bd-811e-5d1073b6d973--199 | 0012Mu_0000000200 | Béton et béton armé | e7be45ff-019b-49bd-811e-5d1073b6d973--200
<Unnamed Element> | Sous-sol | <Unnamed Material> 250 mm | 0012HMu0000000133 | e7be45ff-019b-49bd-811e-5d1073b6d973--133 | 0012Mu_0000000134 | Béton et béton armé | e7be45ff-019b-49bd-811e-5d1073b6d973--134
<Unnamed Element> | Sous-sol | <Unnamed Material> 250 mm | 0012HMu0000000143 | e7be45ff-019b-49bd-811e-5d1073b6d973--143 | 0012Mu_0000000144 | Béton et béton armé | e7be45ff-019b-49bd-811e-5d1073b6d973--144
<Unnamed Element> | Sous-sol | <Unnamed Material> 250 mm | 0012HMu0000000262 | e7be45ff-019b-49bd-811e-5d1073b6d973--262 | 0012Mu_0000000263 | Béton et béton armé | e7be45ff-019b-49bd-811e-5d1073b6d973--263
<Unnamed Element> | Sous-sol | <Unnamed Material> 250 mm | 0012HMu0000000272 | e7be45ff-019b-49bd-811e-5d1073b6d973--272 | 0012Mu_0000000273 | Béton et béton armé | e7be45ff-019b-49bd-811e-5d1073b6d973--273
<Unnamed Element> | Sous-sol | <Unnamed Material> 250 mm | 0012HMu0000000287 | e7be45ff-019b-49bd-811e-5d1073b6d973--287 | 0012Mu_0000000288 | Béton et béton armé | e7be45ff-019b-49bd-811e-5d1073b6d973--288
<Unnamed Element> | Sous-sol | <Unnamed Material> 250 mm | 0012HMu0000000297 | e7be45ff-019b-49bd-811e-5d1073b6d973--297 | 0012Mu_0000000298 | Béton et béton armé | e7be45ff-019b-49bd-811e-5d1073b6d973--298
<Unnamed Element> | Sous-sol | <Unnamed Material> 250 mm | 0012HMu0000000489 | e7be45ff-019b-49bd-811e-5d1073b6d973--489 | 0012Mu_0000000490 | Béton et béton armé | e7be45ff-019b-49bd-811e-5d1073b6d973--490
<Unnamed Element> | Sous-sol | <Unnamed Material> 250 mm | 0012HMu0000000559 | e7be45ff-019b-49bd-811e-5d1073b6d973--559 | 0012Mu_0000000560 | Béton et béton armé | e7be45ff-019b-49bd-811e-5d1073b6d973--560
<Unnamed Element> | Sous-sol | <Unnamed Material> 250 mm | 0012HMu0000000576 | e7be45ff-019b-49bd-811e-5d1073b6d973--576 | 0012Mu_0000000577 | Béton et béton armé | e7be45ff-019b-49bd-811e-5d1073b6d973--577
<Unnamed Element> | Sous-sol | <Unnamed Material> 250 mm | 0012HMu0000000593 | e7be45ff-019b-49bd-811e-5d1073b6d973--593 | 0012Mu_0000000594 | Béton et béton armé | e7be45ff-019b-49bd-811e-5d1073b6d973--594
<Unnamed Element> | Sous-sol | <Unnamed Material> 100 mm | 0012HMu0000000601 | e7be45ff-019b-49bd-811e-5d1073b6d973--601 | 0012Mu_0000000602 | Béton et béton armé | e7be45ff-019b-49bd-811e-5d1073b6d973--602
<Unnamed Element> | Sous-sol | <Unnamed Material> 130 mm | 0012HMu0000000616 | e7be45ff-019b-49bd-811e-5d1073b6d973--616 | 0012Mu_0000000617 | Béton et béton armé | e7be45ff-019b-49bd-811e-5d1073b6d973--617
<Unnamed Element> | Sous-sol | <Unnamed Material> 250 mm | 0012HMu0000000672 | e7be45ff-019b-49bd-811e-5d1073b6d973--672 | 0012Mu_0000000673 | Béton et béton armé | e7be45ff-019b-49bd-811e-5d1073b6d973--673
<Unnamed Element> | Sous-sol | <Unnamed Material> 250 mm | 0012HMu0000000688 | e7be45ff-019b-49bd-811e-5d1073b6d973--688 | 0012Mu_0000000689 | Béton et béton armé | e7be45ff-019b-49bd-811e-5d1073b6d973--689
<Unnamed Element> | Sous-sol | <Unnamed Material> 150 mm | 0012HMu0000000712 | e7be45ff-019b-49bd-811e-5d1073b6d973--712 | 0012Mu_0000000713 | Béton et béton armé | e7be45ff-019b-49bd-811e-5d1073b6d973--713
<Unnamed Element> | Sous-sol | <Unnamed Material> 130 mm | 0012HMu0000000738 | e7be45ff-019b-49bd-811e-5d1073b6d973--738 | 0012Mu_0000000739 | Béton et béton armé | e7be45ff-019b-49bd-811e-5d1073b6d973--739
<Unnamed Element> | Sous-sol | <Unnamed Material> 130 mm | 0012HMu0000000755 | e7be45ff-019b-49bd-811e-5d1073b6d973--755 | 0012Mu_0000000756 | Béton et béton armé | e7be45ff-019b-49bd-811e-5d1073b6d973--756
<Unnamed Element> | Sous-sol | <Unnamed Material> 130 mm | 0012HMu0000000765 | e7be45ff-019b-49bd-811e-5d1073b6d973--765 | 0012Mu_0000000766 | Béton et béton armé | e7be45ff-019b-49bd-811e-5d1073b6d973--766
<Unnamed Element> | Sous-sol | <Unnamed Material> 200 mm | 0012HMu0000000795 | e7be45ff-019b-49bd-811e-5d1073b6d973--795 | 0012Mu_0000000796 | Béton et béton armé | e7be45ff-019b-49bd-811e-5d1073b6d973--796
<Unnamed Element> | Sous-sol | <Unnamed Material> 200 mm | 0012HMu0000000871 | e7be45ff-019b-49bd-811e-5d1073b6d973--871 | 0012Mu_0000000872 | Béton et béton armé | e7be45ff-019b-49bd-811e-5d1073b6d973--872
<Unnamed Element> | Sous-sol | <Unnamed Material> 200 mm | 0012HMu0000000849 | e7be45ff-019b-49bd-811e-5d1073b6d973--849 | 0012Mu_0000000850 | Béton et béton armé | e7be45ff-019b-49bd-811e-5d1073b6d973--850
<Unnamed Element> | Sous-sol | <Unnamed Material> 200 mm | 0012HMu0000000935 | e7be45ff-019b-49bd-811e-5d1073b6d973--935 | 0012Mu_0000000936 | Béton et béton armé | e7be45ff-019b-49bd-811e-5d1073b6d973--936
<Unnamed Element> | Sous-sol | <Unnamed Material> 200 mm | 0012HMu0000001016 | e7be45ff-019b-49bd-811e-5d1073b6d973--1016 | 0012Mu_0000001017 | Béton et béton armé | e7be45ff-019b-49bd-811e-5d1073b6d973--1017
<Unnamed Element> | Sous-sol | <Unnamed Material> 200 mm | 0012HMu0000001059 | e7be45ff-019b-49bd-811e-5d1073b6d973--1059 | 0012Mu_0000001060 | Béton et béton armé | e7be45ff-019b-49bd-811e-5d1073b6d973--1060
<Unnamed Element> | Sous-sol | <Unnamed Material> 200 mm | 0012HMu0000001069 | e7be45ff-019b-49bd-811e-5d1073b6d973--1069 | 0012Mu_0000001070 | Béton et béton armé | e7be45ff-019b-49bd-811e-5d1073b6d973--1070
<Unnamed Element> | Sous-sol | <Unnamed Material> 200 mm | 0012HMu0000001080 | e7be45ff-019b-49bd-811e-5d1073b6d973--1080 | 0012Mu_0000001081 | Béton et béton armé | e7be45ff-019b-49bd-811e-5d1073b6d973--1081
<Unnamed Element> | Sous-sol | <Unnamed Material> 250 mm | 0012HMu0000001314 | e7be45ff-019b-49bd-811e-5d1073b6d973--1314 | 0012Mu_0000001315 | Menuiserie | e7be45ff-019b-49bd-811e-5d1073b6d973--1315
<Unnamed Element> | Sous-sol | <Unnamed Material> 250 mm | 0012HMu0000001306 | e7be45ff-019b-49bd-811e-5d1073b6d973--1306 | 0012Mu_0000001307 | Menuiserie | e7be45ff-019b-49bd-811e-5d1073b6d973--1307
<Unnamed Element> | Sous-sol | <Unnamed Material> 250 mm | 0012HMu0000001301 | e7be45ff-019b-49bd-811e-5d1073b6d973--1301 | 0012Mu_0000001302 | Menuiserie | e7be45ff-019b-49bd-811e-5d1073b6d973--1302
<Unnamed Element> | Sous-sol | <Unnamed Material> 250 mm | 0012HMu0000001295 | e7be45ff-019b-49bd-811e-5d1073b6d973--1295 | 0012Mu_0000001296 | Menuiserie | e7be45ff-019b-49bd-811e-5d1073b6d973--1296
<Unnamed Element> | Sous-sol | <Unnamed Material> 250 mm | 0012HMu0000001373 | e7be45ff-019b-49bd-811e-5d1073b6d973--1373 | 0012Mu_0000001374 | Menuiserie | e7be45ff-019b-49bd-811e-5d1073b6d973--1374
<Unnamed Element> | Sous-sol | <Unnamed Material> 250 mm | 0012HMu0000001367 | e7be45ff-019b-49bd-811e-5d1073b6d973--1367 | 0012Mu_0000001368 | Menuiserie | e7be45ff-019b-49bd-811e-5d1073b6d973--1368
<Unnamed Element> | Sous-sol | <Unnamed Material> 250 mm | 0013HMu0000000207 | f5a8dc2b-c76c-4dda-bb0b-31f6e3ff0e0c--207 | 0013Mu_0000000208 | Béton et béton armé | f5a8dc2b-c76c-4dda-bb0b-31f6e3ff0e0c--208
<Unnamed Element> | Sous-sol | <Unnamed Material> 250 mm | 0013HMu0000000290 | f5a8dc2b-c76c-4dda-bb0b-31f6e3ff0e0c--290 | 0013Mu_0000000291 | Béton et béton armé | f5a8dc2b-c76c-4dda-bb0b-31f6e3ff0e0c--291
<Unnamed Element> | Sous-sol | <Unnamed Material> 250 mm | 0013HMu0000000339 | f5a8dc2b-c76c-4dda-bb0b-31f6e3ff0e0c--339 | 0013Mu_0000000340 | Béton et béton armé | f5a8dc2b-c76c-4dda-bb0b-31f6e3ff0e0c--340
<Unnamed Element> | Sous-sol | <Unnamed Material> 250 mm | 0013HMu0000000213 | f5a8dc2b-c76c-4dda-bb0b-31f6e3ff0e0c--213 | 0013Mu_0000000214 | Béton et béton armé | f5a8dc2b-c76c-4dda-bb0b-31f6e3ff0e0c--214
<Unnamed Element> | Rez-de-chaussée | <Unnamed Material> 200 mm | 0022HMu0000000029 | 0e2b27f9-10d3-4386-be4d-cd432914257b--29 | 0022Mu_0000000030 | Béton et béton armé | 0e2b27f9-10d3-4386-be4d-cd432914257b--30
<Unnamed Element> | Rez-de-chaussée | <Unnamed Material> 200 mm | 0022HMu0000000034 | 0e2b27f9-10d3-4386-be4d-cd432914257b--34 | 0022Mu_0000000035 | Béton et béton armé | 0e2b27f9-10d3-4386-be4d-cd432914257b--35
<Unnamed Element> | Rez-de-chaussée | <Unnamed Material> 200 mm | 0022HMu0000000039 | 0e2b27f9-10d3-4386-be4d-cd432914257b--39 | 0022Mu_0000000040 | Béton et béton armé | 0e2b27f9-10d3-4386-be4d-cd432914257b--40
<Unnamed Element> | Rez-de-chaussée | <Unnamed Material> 200 mm | 0022HMu0000000050 | 0e2b27f9-10d3-4386-be4d-cd432914257b--50 | 0022Mu_0000000051 | Béton et béton armé | 0e2b27f9-10d3-4386-be4d-cd432914257b--51
<Unnamed Element> | Rez-de-chaussée | <Unnamed Material> 200 mm | 0022HMu0000000055 | 0e2b27f9-10d3-4386-be4d-cd432914257b--55 | 0022Mu_0000000056 | Béton et béton armé | 0e2b27f9-10d3-4386-be4d-cd432914257b--56
<Unnamed Element> | Rez-de-chaussée | <Unnamed Material> 200 mm | 0022HMu0000000069 | 0e2b27f9-10d3-4386-be4d-cd432914257b--69 | 0022Mu_0000000070 | Béton et béton armé | 0e2b27f9-10d3-4386-be4d-cd432914257b--70
<Unnamed Element> | Rez-de-chaussée | <Unnamed Material> 350 mm | 0022HMu0000000133 | 0e2b27f9-10d3-4386-be4d-cd432914257b--133 | 0022Mu_0000000134 | Béton et béton armé | 0e2b27f9-10d3-4386-be4d-cd432914257b--134
<Unnamed Element> | Rez-de-chaussée | <Unnamed Material> 200 mm | 0022HMu0000000148 | 0e2b27f9-10d3-4386-be4d-cd432914257b--148 | 0022Mu_0000000149 | Béton et béton armé | 0e2b27f9-10d3-4386-be4d-cd432914257b--149
<Unnamed Element> | Rez-de-chaussée | <Unnamed Material> 200 mm | 0022HMu0000000157 | 0e2b27f9-10d3-4386-be4d-cd432914257b--157 | 0022Mu_0000000158 | Béton et béton armé | 0e2b27f9-10d3-4386-be4d-cd432914257b--158
<Unnamed Element> | Rez-de-chaussée | <Unnamed Material> 200 mm | 0022HMu0000000168 | 0e2b27f9-10d3-4386-be4d-cd432914257b--168 | 0022Mu_0000000169 | Béton et béton armé | 0e2b27f9-10d3-4386-be4d-cd432914257b--169
<Unnamed Element> | Rez-de-chaussée | <Unnamed Material> 200 mm | 0022HMu0000000178 | 0e2b27f9-10d3-4386-be4d-cd432914257b--178 | 0022Mu_0000000179 | Béton et béton armé | 0e2b27f9-10d3-4386-be4d-cd432914257b--179
<Unnamed Element> | Rez-de-chaussée | <Unnamed Material> 200 mm | 0022HMu0000000186 | 0e2b27f9-10d3-4386-be4d-cd432914257b--186 | 0022Mu_0000000187 | Béton et béton armé | 0e2b27f9-10d3-4386-be4d-cd432914257b--187
<Unnamed Element> | Rez-de-chaussée | <Unnamed Material> 200 mm | 0022HMu0000000194 | 0e2b27f9-10d3-4386-be4d-cd432914257b--194 | 0022Mu_0000000195 | Béton et béton armé | 0e2b27f9-10d3-4386-be4d-cd432914257b--195
<Unnamed Element> | Rez-de-chaussée | <Unnamed Material> 200 mm | 0022HMu0000000207 | 0e2b27f9-10d3-4386-be4d-cd432914257b--207 | 0022Mu_0000000208 | Béton et béton armé | 0e2b27f9-10d3-4386-be4d-cd432914257b--208
<Unnamed Element> | Rez-de-chaussée | <Unnamed Material> 200 mm | 0022HMu0000000217 | 0e2b27f9-10d3-4386-be4d-cd432914257b--217 | 0022Mu_0000000218 | Béton et béton armé | 0e2b27f9-10d3-4386-be4d-cd432914257b--218
<Unnamed Element> | Rez-de-chaussée | <Unnamed Material> 150 mm | 0022HMu0000000258 | 0e2b27f9-10d3-4386-be4d-cd432914257b--258 | 0022Mu_0000000259 | Béton et béton armé | 0e2b27f9-10d3-4386-be4d-cd432914257b--259
<Unnamed Element> | Rez-de-chaussée | <Unnamed Material> 150 mm | 0022HMu0000000269 | 0e2b27f9-10d3-4386-be4d-cd432914257b--269 | 0022Mu_0000000270 | Béton et béton armé | 0e2b27f9-10d3-4386-be4d-cd432914257b--270
<Unnamed Element> | Rez-de-chaussée | <Unnamed Material> 200 mm | 0022HMu0000000290 | 0e2b27f9-10d3-4386-be4d-cd432914257b--290 | 0022Mu_0000000291 | Béton et béton armé | 0e2b27f9-10d3-4386-be4d-cd432914257b--291
<Unnamed Element> | Rez-de-chaussée | <Unnamed Material> 200 mm | 0027HMu0000000015 | d315fca0-df44-48a9-a052-42f8cd2f5afa--15 | 0027Mu_0000000016 | Béton et béton armé | d315fca0-df44-48a9-a052-42f8cd2f5afa--16
<Unnamed Element> | Rez-de-chaussée | <Unnamed Material> 200 mm | 0027HMu0000000116 | d315fca0-df44-48a9-a052-42f8cd2f5afa--116 | 0027Mu_0000000117 | Béton et béton armé | d315fca0-df44-48a9-a052-42f8cd2f5afa--117
<Unnamed Element> | 1. Etage supérieur | <Unnamed Material> 200 mm | 0032HMu0000003564 | 6a1e8f65-a2b8-4168-b325-3206246c0164--3564 | 0032Mu_0000003565 | Béton et béton armé | 6a1e8f65-a2b8-4168-b325-3206246c0164--3565
<Unnamed Element> | 1. Etage supérieur | <Unnamed Material> 200 mm | 0032HMu0000003554 | 6a1e8f65-a2b8-4168-b325-3206246c0164--3554 | 0032Mu_0000003555 | Béton et béton armé | 6a1e8f65-a2b8-4168-b325-3206246c0164--3555
<Unnamed Element> | 1. Etage supérieur | <Unnamed Material> 200 mm | 0032HMu0000003543 | 6a1e8f65-a2b8-4168-b325-3206246c0164--3543 | 0032Mu_0000003544 | Béton et béton armé | 6a1e8f65-a2b8-4168-b325-3206246c0164--3544
<Unnamed Element> | 1. Etage supérieur | <Unnamed Material> 200 mm | 0032HMu0000003679 | 6a1e8f65-a2b8-4168-b325-3206246c0164--3679 | 0032Mu_0000003680 | Béton et béton armé | 6a1e8f65-a2b8-4168-b325-3206246c0164--3680
<Unnamed Element> | 1. Etage supérieur | <Unnamed Material> 200 mm | 0032HMu0000003641 | 6a1e8f65-a2b8-4168-b325-3206246c0164--3641 | 0032Mu_0000003642 | Béton et béton armé | 6a1e8f65-a2b8-4168-b325-3206246c0164--3642
<Unnamed Element> | 1. Etage supérieur | <Unnamed Material> 200 mm | 0032HMu0000003674 | 6a1e8f65-a2b8-4168-b325-3206246c0164--3674 | 0032Mu_0000003675 | Béton et béton armé | 6a1e8f65-a2b8-4168-b325-3206246c0164--3675
<Unnamed Element> | 1. Etage supérieur | <Unnamed Material> 100 mm | 0032HMu0000003755 | 6a1e8f65-a2b8-4168-b325-3206246c0164--3755 | 0032Mu_0000003756 | Béton et béton armé | 6a1e8f65-a2b8-4168-b325-3206246c0164--3756
<Unnamed Element> | 1. Etage supérieur | <Unnamed Material> 200 mm | 0032HMu0000003631 | 6a1e8f65-a2b8-4168-b325-3206246c0164--3631 | 0032Mu_0000003632 | Béton et béton armé | 6a1e8f65-a2b8-4168-b325-3206246c0164--3632
<Unnamed Element> | 1. Etage supérieur | <Unnamed Material> 200 mm | 0032HMu0000003626 | 6a1e8f65-a2b8-4168-b325-3206246c0164--3626 | 0032Mu_0000003627 | Béton et béton armé | 6a1e8f65-a2b8-4168-b325-3206246c0164--3627
<Unnamed Element> | 1. Etage supérieur | <Unnamed Material> 200 mm | 0032HMu0000003651 | 6a1e8f65-a2b8-4168-b325-3206246c0164--3651 | 0032Mu_0000003652 | Béton et béton armé | 6a1e8f65-a2b8-4168-b325-3206246c0164--3652
<Unnamed Element> | 1. Etage supérieur | <Unnamed Material> 150 mm | 0032HMu0000003707 | 6a1e8f65-a2b8-4168-b325-3206246c0164--3707 | 0032Mu_0000003708 | Béton et béton armé | 6a1e8f65-a2b8-4168-b325-3206246c0164--3708
<Unnamed Element> | 1. Etage supérieur | <Unnamed Material> 200 mm | 0032HMu0000003662 | 6a1e8f65-a2b8-4168-b325-3206246c0164--3662 | 0032Mu_0000003663 | Béton et béton armé | 6a1e8f65-a2b8-4168-b325-3206246c0164--3663
<Unnamed Element> | 1. Etage supérieur | <Unnamed Material> 150 mm | 0032HMu0000003727 | 6a1e8f65-a2b8-4168-b325-3206246c0164--3727 | 0032Mu_0000003728 | Béton et béton armé | 6a1e8f65-a2b8-4168-b325-3206246c0164--3728
<Unnamed Element> | 1. Etage supérieur | <Unnamed Material> 150 mm | 0032HMu0000003717 | 6a1e8f65-a2b8-4168-b325-3206246c0164--3717 | 0032Mu_0000003718 | Béton et béton armé | 6a1e8f65-a2b8-4168-b325-3206246c0164--3718
<Unnamed Element> | 1. Etage supérieur | <Unnamed Material> 200 mm | 0032HMu0000003606 | 6a1e8f65-a2b8-4168-b325-3206246c0164--3606 | 0032Mu_0000003607 | Béton et béton armé | 6a1e8f65-a2b8-4168-b325-3206246c0164--3607
<Unnamed Element> | 1. Etage supérieur | <Unnamed Material> 200 mm | 0032HMu0000003587 | 6a1e8f65-a2b8-4168-b325-3206246c0164--3587 | 0032Mu_0000003588 | Béton et béton armé | 6a1e8f65-a2b8-4168-b325-3206246c0164--3588
<Unnamed Element> | 1. Etage supérieur | <Unnamed Material> 200 mm | 0032HMu0000003577 | 6a1e8f65-a2b8-4168-b325-3206246c0164--3577 | 0032Mu_0000003578 | Béton et béton armé | 6a1e8f65-a2b8-4168-b325-3206246c0164--3578
<Unnamed Element> | 1. Etage supérieur | <Unnamed Material> 200 mm | 0032HMu0000003595 | 6a1e8f65-a2b8-4168-b325-3206246c0164--3595 | 0032Mu_0000003596 | Béton et béton armé | 6a1e8f65-a2b8-4168-b325-3206246c0164--3596
<Unnamed Element> | 1. Etage supérieur | <Unnamed Material> 200 mm | 0032HMu0000003538 | 6a1e8f65-a2b8-4168-b325-3206246c0164--3538 | 0032Mu_0000003539 | Béton et béton armé | 6a1e8f65-a2b8-4168-b325-3206246c0164--3539
<Unnamed Element> | 2. Etage supérieur | <Unnamed Material> 150 mm | 0042HMu0000000618 | 90a796d3-f0ad-4bd1-a568-830c8568f6ce--618 | 0042Mu_0000000619 | Menuiserie | 90a796d3-f0ad-4bd1-a568-830c8568f6ce--619
<Unnamed Element> | 2. Etage supérieur | <Unnamed Material> 150 mm | 0042HMu0000000640 | 90a796d3-f0ad-4bd1-a568-830c8568f6ce--640 | 0042Mu_0000000641 | Menuiserie | 90a796d3-f0ad-4bd1-a568-830c8568f6ce--641
<Unnamed Element> | 2. Etage supérieur | <Unnamed Material> 0.5 mm | 0042HMu0000000211 | 90a796d3-f0ad-4bd1-a568-830c8568f6ce--211 | 0042Mu_0000000212 | Menuiserie | 90a796d3-f0ad-4bd1-a568-830c8568f6ce--212
<Unnamed Element> | 2. Etage supérieur | <Unnamed Material> 201 mm | 0042HMu0000000299 | 90a796d3-f0ad-4bd1-a568-830c8568f6ce--299 | 0042Mu_0000000300 | Menuiserie | 90a796d3-f0ad-4bd1-a568-830c8568f6ce--300
<Unnamed Element> | 2. Etage supérieur | <Unnamed Material> 200 mm | 0042HMu0000000333 | 90a796d3-f0ad-4bd1-a568-830c8568f6ce--333 | 0042Mu_0000000334 | Menuiserie | 90a796d3-f0ad-4bd1-a568-830c8568f6ce--334
<Unnamed Element> | 2. Etage supérieur | <Unnamed Material> 200 mm | 0042HMu0000000323 | 90a796d3-f0ad-4bd1-a568-830c8568f6ce--323 | 0042Mu_0000000324 | Menuiserie | 90a796d3-f0ad-4bd1-a568-830c8568f6ce--324
<Unnamed Element> | 2. Etage supérieur | <Unnamed Material> 150 mm | 0042HMu0000000628 | 90a796d3-f0ad-4bd1-a568-830c8568f6ce--628 | 0042Mu_0000000629 | Menuiserie | 90a796d3-f0ad-4bd1-a568-830c8568f6ce--629
<Unnamed Element> | 2. Etage supérieur | <Unnamed Material> 201 mm | 0042HMu0000000279 | 90a796d3-f0ad-4bd1-a568-830c8568f6ce--279 | 0042Mu_0000000280 | Menuiserie | 90a796d3-f0ad-4bd1-a568-830c8568f6ce--280
<Unnamed Element> | 2. Etage supérieur | <Unnamed Material> 201 mm | 0042HMu0000000274 | 90a796d3-f0ad-4bd1-a568-830c8568f6ce--274 | 0042Mu_0000000275 | Menuiserie | 90a796d3-f0ad-4bd1-a568-830c8568f6ce--275
<Unnamed Element> | 2. Etage supérieur | <Unnamed Material> 100 mm | 0042HMu0000000659 | 90a796d3-f0ad-4bd1-a568-830c8568f6ce--659 | 0042Mu_0000000660 | Menuiserie | 90a796d3-f0ad-4bd1-a568-830c8568f6ce--660
<Unnamed Element> | 2. Etage supérieur | <Unnamed Material> 201 mm | 0042HMu0000000304 | 90a796d3-f0ad-4bd1-a568-830c8568f6ce--304 | 0042Mu_0000000305 | Menuiserie | 90a796d3-f0ad-4bd1-a568-830c8568f6ce--305
<Unnamed Element> | 2. Etage supérieur | <Unnamed Material> 200 mm | 0042HMu0000000338 | 90a796d3-f0ad-4bd1-a568-830c8568f6ce--338 | 0042Mu_0000000339 | Menuiserie | 90a796d3-f0ad-4bd1-a568-830c8568f6ce--339
<Unnamed Element> | 2. Etage supérieur | <Unnamed Material> 200 mm | 0042HMu0000000597 | 90a796d3-f0ad-4bd1-a568-830c8568f6ce--597 | 0042Mu_0000000598 | Menuiserie | 90a796d3-f0ad-4bd1-a568-830c8568f6ce--598
<Unnamed Element> | 2. Etage supérieur | <Unnamed Material> 200 mm | 0042HMu0000000352 | 90a796d3-f0ad-4bd1-a568-830c8568f6ce--352 | 0042Mu_0000000353 | Menuiserie | 90a796d3-f0ad-4bd1-a568-830c8568f6ce--353
<Unnamed Element> | 2. Etage supérieur | <Unnamed Material> 200 mm | 0042HMu0000000998 | 90a796d3-f0ad-4bd1-a568-830c8568f6ce--998 | 0042Mu_0000000999 | Menuiserie | 90a796d3-f0ad-4bd1-a568-830c8568f6ce--999
2 x <Unnamed Element> | 2. Etage supérieur | <Unnamed Material> 200 mm | 0042HMu0000000115 | 90a796d3-f0ad-4bd1-a568-830c8568f6ce--115 | 0042Mu_0000000116 | Menuiserie | 90a796d3-f0ad-4bd1-a568-830c8568f6ce--116
<Unnamed Element> | 2. Etage supérieur | <Unnamed Material> 200 mm | 0042HMu0000000562 | 90a796d3-f0ad-4bd1-a568-830c8568f6ce--562 | 0042Mu_0000000563 | Menuiserie | 90a796d3-f0ad-4bd1-a568-830c8568f6ce--563
<Unnamed Element> | 2. Etage supérieur | <Unnamed Material> 200 mm | 0042HMu0000000532 | 90a796d3-f0ad-4bd1-a568-830c8568f6ce--532 | 0042Mu_0000000533 | Menuiserie | 90a796d3-f0ad-4bd1-a568-830c8568f6ce--533
<Unnamed Element> | 2. Etage supérieur | <Unnamed Material> 200 mm | 0042HMu0000000390 | 90a796d3-f0ad-4bd1-a568-830c8568f6ce--390 | 0042Mu_0000000391 | Menuiserie | 90a796d3-f0ad-4bd1-a568-830c8568f6ce--391
<Unnamed Element> | 2. Etage supérieur | <Unnamed Material> 200 mm | 0042HMu0000000964 | 90a796d3-f0ad-4bd1-a568-830c8568f6ce--964 | 0042Mu_0000000965 | Menuiserie | 90a796d3-f0ad-4bd1-a568-830c8568f6ce--965
<Unnamed Element> | 2. Etage supérieur | <Unnamed Material> 200 mm | 0042HMu0000001066 | 90a796d3-f0ad-4bd1-a568-830c8568f6ce--1066 | 0042Mu_0000001067 | Menuiserie | 90a796d3-f0ad-4bd1-a568-830c8568f6ce--1067
<Unnamed Element> | 2. Etage supérieur | <Unnamed Material> 200 mm | 0042HMu0000000175 | 90a796d3-f0ad-4bd1-a568-830c8568f6ce--175 | 0042Mu_0000000176 | Menuiserie | 90a796d3-f0ad-4bd1-a568-830c8568f6ce--176
<Unnamed Element> | 3. Etage supérieur | <Unnamed Material> 200 mm | 0052HMu0000000084 | 435ab560-3884-4131-b1cc-7aba0e0d0a30--84 | 0052Mu_0000000085 | Menuiserie | 435ab560-3884-4131-b1cc-7aba0e0d0a30--85
<Unnamed Element> | 3. Etage supérieur | <Unnamed Material> 200 mm | 0052HMu0000000543 | 435ab560-3884-4131-b1cc-7aba0e0d0a30--543 | 0052Mu_0000000544 | Menuiserie | 435ab560-3884-4131-b1cc-7aba0e0d0a30--544
<Unnamed Element> | 3. Etage supérieur | <Unnamed Material> 200 mm | 0052HMu0000000220 | 435ab560-3884-4131-b1cc-7aba0e0d0a30--220 | 0052Mu_0000000221 | Menuiserie | 435ab560-3884-4131-b1cc-7aba0e0d0a30--221
<Unnamed Element> | 3. Etage supérieur | <Unnamed Material> 200 mm | 0052HMu0000000233 | 435ab560-3884-4131-b1cc-7aba0e0d0a30--233 | 0052Mu_0000000234 | Menuiserie | 435ab560-3884-4131-b1cc-7aba0e0d0a30--234
<Unnamed Element> | 3. Etage supérieur | <Unnamed Material> 200 mm | 0052HMu0000000225 | 435ab560-3884-4131-b1cc-7aba0e0d0a30--225 | 0052Mu_0000000226 | Menuiserie | 435ab560-3884-4131-b1cc-7aba0e0d0a30--226
<Unnamed Element> | 3. Etage supérieur | <Unnamed Material> 200 mm | 0052HMu0000000241 | 435ab560-3884-4131-b1cc-7aba0e0d0a30--241 | 0052Mu_0000000242 | Menuiserie | 435ab560-3884-4131-b1cc-7aba0e0d0a30--242
<Unnamed Element> | 3. Etage supérieur | <Unnamed Material> 200 mm | 0052HMu0000000561 | 435ab560-3884-4131-b1cc-7aba0e0d0a30--561 | 0052Mu_0000000562 | Menuiserie | 435ab560-3884-4131-b1cc-7aba0e0d0a30--562
<Unnamed Element> | 3. Etage supérieur | <Unnamed Material> 200 mm | 0052HMu0000000099 | 435ab560-3884-4131-b1cc-7aba0e0d0a30--99 | 0052Mu_0000000100 | Menuiserie | 435ab560-3884-4131-b1cc-7aba0e0d0a30--100
<Unnamed Element> | 3. Etage supérieur | <Unnamed Material> 200 mm | 0052HMu0000000043 | 435ab560-3884-4131-b1cc-7aba0e0d0a30--43 | 0052Mu_0000000044 | Menuiserie | 435ab560-3884-4131-b1cc-7aba0e0d0a30--44
<Unnamed Element> | 3. Etage supérieur | <Unnamed Material> 200 mm | 0052HMu0000000031 | 435ab560-3884-4131-b1cc-7aba0e0d0a30--31 | 0052Mu_0000000032 | Menuiserie | 435ab560-3884-4131-b1cc-7aba0e0d0a30--32
<Unnamed Element> | 3. Etage supérieur | <Unnamed Material> 200 mm | 0052HMu0000000023 | 435ab560-3884-4131-b1cc-7aba0e0d0a30--23 | 0052Mu_0000000024 | Menuiserie | 435ab560-3884-4131-b1cc-7aba0e0d0a30--24
<Unnamed Element> | 3. Etage supérieur | <Unnamed Material> 200 mm | 0052HMu0000000013 | 435ab560-3884-4131-b1cc-7aba0e0d0a30--13 | 0052Mu_0000000014 | Menuiserie | 435ab560-3884-4131-b1cc-7aba0e0d0a30--14
<Unnamed Element> | 3. Etage supérieur | <Unnamed Material> 200 mm | 0052HMu0000000209 | 435ab560-3884-4131-b1cc-7aba0e0d0a30--209 | 0052Mu_0000000210 | Menuiserie | 435ab560-3884-4131-b1cc-7aba0e0d0a30--210
<Unnamed Element> | 3. Etage supérieur | <Unnamed Material> 200 mm | 0052HMu0000000133 | 435ab560-3884-4131-b1cc-7aba0e0d0a30--133 | 0052Mu_0000000134 | Menuiserie | 435ab560-3884-4131-b1cc-7aba0e0d0a30--134
<Unnamed Element> | 3. Etage supérieur | <Unnamed Material> 200 mm | 0052HMu0000000115 | 435ab560-3884-4131-b1cc-7aba0e0d0a30--115 | 0052Mu_0000000116 | Menuiserie | 435ab560-3884-4131-b1cc-7aba0e0d0a30--116
<Unnamed Element> | 3. Etage supérieur | <Unnamed Material> 200 mm | 0052HMu0000000120 | 435ab560-3884-4131-b1cc-7aba0e0d0a30--120 | 0052Mu_0000000121 | Menuiserie | 435ab560-3884-4131-b1cc-7aba0e0d0a30--121
<Unnamed Element> | 3. Etage supérieur | <Unnamed Material> 200 mm | 0052HMu0000000151 | 435ab560-3884-4131-b1cc-7aba0e0d0a30--151 | 0052Mu_0000000152 | Menuiserie | 435ab560-3884-4131-b1cc-7aba0e0d0a30--152
<Unnamed Element> | 3. Etage supérieur | <Unnamed Material> 101 mm | 0052HMu0000000294 | 435ab560-3884-4131-b1cc-7aba0e0d0a30--294 | 0052Mu_0000000295 | Menuiserie | 435ab560-3884-4131-b1cc-7aba0e0d0a30--295
<Unnamed Element> | 3. Etage supérieur | <Unnamed Material> 200 mm | 0052HMu0000000159 | 435ab560-3884-4131-b1cc-7aba0e0d0a30--159 | 0052Mu_0000000160 | Menuiserie | 435ab560-3884-4131-b1cc-7aba0e0d0a30--160
<Unnamed Element> | 3. Etage supérieur | <Unnamed Material> 150 mm | 0052HMu0000000179 | 435ab560-3884-4131-b1cc-7aba0e0d0a30--179 | 0052Mu_0000000180 | Menuiserie | 435ab560-3884-4131-b1cc-7aba0e0d0a30--180
<Unnamed Element> | 3. Etage supérieur | <Unnamed Material> 150 mm | 0052HMu0000000189 | 435ab560-3884-4131-b1cc-7aba0e0d0a30--189 | 0052Mu_0000000190 | Menuiserie | 435ab560-3884-4131-b1cc-7aba0e0d0a30--190
<Unnamed Element> | 3. Etage supérieur | <Unnamed Material> 200 mm | 0052HMu0000000125 | 435ab560-3884-4131-b1cc-7aba0e0d0a30--125 | 0052Mu_0000000126 | Menuiserie | 435ab560-3884-4131-b1cc-7aba0e0d0a30--126
<Unnamed Element> | 3. Etage supérieur | <Unnamed Material> 150 mm | 0052HMu0000000323 | 435ab560-3884-4131-b1cc-7aba0e0d0a30--323 | 0052Mu_0000000324 | Menuiserie | 435ab560-3884-4131-b1cc-7aba0e0d0a30--324
<Unnamed Element> | 3. Etage supérieur | <Unnamed Material> 200 mm | 0052HMu0000000599 | 435ab560-3884-4131-b1cc-7aba0e0d0a30--599 | 0052Mu_0000000600 | Menuiserie | 435ab560-3884-4131-b1cc-7aba0e0d0a30--600
<Unnamed Element> | 3. Etage supérieur | <Unnamed Material> 200 mm | 0052HMu0000000644 | 435ab560-3884-4131-b1cc-7aba0e0d0a30--644 | 0052Mu_0000000645 | Menuiserie | 435ab560-3884-4131-b1cc-7aba0e0d0a30--645
<Unnamed Element> | 3. Etage supérieur | <Unnamed Material> 200 mm | 0052HMu0000000655 | 435ab560-3884-4131-b1cc-7aba0e0d0a30--655 | 0052Mu_0000000656 | Menuiserie | 435ab560-3884-4131-b1cc-7aba0e0d0a30--656
<Unnamed Element> | 4. Etage supérieur | <Unnamed Material> 200 mm | 0062HMu0000000252 | 347db150-1122-4b3f-bc21-631404b16890--252 | 0062Mu_0000000275 | Menuiserie | 347db150-1122-4b3f-bc21-631404b16890--275
<Unnamed Element> | 4. Etage supérieur | <Unnamed Material> 200 mm | 0062HMu0000000514 | 347db150-1122-4b3f-bc21-631404b16890--514 | 0062Mu_0000000537 | Menuiserie | 347db150-1122-4b3f-bc21-631404b16890--537
<Unnamed Element> | 4. Etage supérieur | <Unnamed Material> 200 mm | 0062HMu0000000272 | 347db150-1122-4b3f-bc21-631404b16890--272 | 0062Mu_0000000277 | Menuiserie | 347db150-1122-4b3f-bc21-631404b16890--277
<Unnamed Element> | 4. Etage supérieur | <Unnamed Material> 200 mm | 0062HMu0000000256 | 347db150-1122-4b3f-bc21-631404b16890--256 | 0062Mu_0000000511 | Menuiserie | 347db150-1122-4b3f-bc21-631404b16890--511
<Unnamed Element> | 4. Etage supérieur | <Unnamed Material> 200 mm | 0062HMu0000000250 | 347db150-1122-4b3f-bc21-631404b16890--250 | 0062Mu_0000000482 | Menuiserie | 347db150-1122-4b3f-bc21-631404b16890--482
<Unnamed Element> | 4. Etage supérieur | <Unnamed Material> 200 mm | 0062HMu0000000479 | 347db150-1122-4b3f-bc21-631404b16890--479 | 0062Mu_0000000491 | Menuiserie | 347db150-1122-4b3f-bc21-631404b16890--491
<Unnamed Element> | 4. Etage supérieur | <Unnamed Material> 200 mm | 0062HMu0000000509 | 347db150-1122-4b3f-bc21-631404b16890--509 | 0062Mu_0000000548 | Menuiserie | 347db150-1122-4b3f-bc21-631404b16890--548
<Unnamed Element> | 4. Etage supérieur | <Unnamed Material> 150 mm | 0062HMu0000000299 | 347db150-1122-4b3f-bc21-631404b16890--299 | 0062Mu_0000000302 | Menuiserie | 347db150-1122-4b3f-bc21-631404b16890--302
<Unnamed Element> | 4. Etage supérieur | <Unnamed Material> 200 mm | 0062HMu0000000258 | 347db150-1122-4b3f-bc21-631404b16890--258 | 0062Mu_0000000296 | Menuiserie | 347db150-1122-4b3f-bc21-631404b16890--296
<Unnamed Element> | 4. Etage supérieur | <Unnamed Material> 200 mm | 0062HMu0000000260 | 347db150-1122-4b3f-bc21-631404b16890--260 | 0062Mu_0000000294 | Menuiserie | 347db150-1122-4b3f-bc21-631404b16890--294
<Unnamed Element> | 4. Etage supérieur | <Unnamed Material> 150 mm | 0062HMu0000000263 | 347db150-1122-4b3f-bc21-631404b16890--263 | 0062Mu_0000000268 | Menuiserie | 347db150-1122-4b3f-bc21-631404b16890--268
<Unnamed Element> | 4. Etage supérieur | <Unnamed Material> 150 mm | 0062HMu0000000265 | 347db150-1122-4b3f-bc21-631404b16890--265 | 0062Mu_0000000270 | Menuiserie | 347db150-1122-4b3f-bc21-631404b16890--270
<Unnamed Element> | 4. Etage supérieur | <Unnamed Material> 200 mm | 0062HMu0000000234 | 347db150-1122-4b3f-bc21-631404b16890--234 | 0062Mu_0000000310 | Menuiserie | 347db150-1122-4b3f-bc21-631404b16890--310
<Unnamed Element> | 4. Etage supérieur | <Unnamed Material> 200 mm | 0062HMu0000000242 | 347db150-1122-4b3f-bc21-631404b16890--242 | 0062Mu_0000000432 | Menuiserie | 347db150-1122-4b3f-bc21-631404b16890--432
<Unnamed Element> | 4. Etage supérieur | <Unnamed Material> 200 mm | 0062HMu0000000427 | 347db150-1122-4b3f-bc21-631404b16890--427 | 0062Mu_0000000475 | Menuiserie | 347db150-1122-4b3f-bc21-631404b16890--475
<Unnamed Element> | 4. Etage supérieur | <Unnamed Material> 200 mm | 0062HMu0000000284 | 347db150-1122-4b3f-bc21-631404b16890--284 | 0062Mu_0000000580 | Menuiserie | 347db150-1122-4b3f-bc21-631404b16890--580
<Unnamed Element> | 4. Etage supérieur | <Unnamed Material> 200 mm | 0062HMu0000000438 | 347db150-1122-4b3f-bc21-631404b16890--438 | 0062Mu_0000000464 | Menuiserie | 347db150-1122-4b3f-bc21-631404b16890--464
<Unnamed Element> | 4. Etage supérieur | <Unnamed Material> 200 mm | 0062HMu0000000279 | 347db150-1122-4b3f-bc21-631404b16890--279 | 0062Mu_0000000434 | Menuiserie | 347db150-1122-4b3f-bc21-631404b16890--434
<Unnamed Element> | 4. Etage supérieur | <Unnamed Material> 200 mm | 0062HMu0000000248 | 347db150-1122-4b3f-bc21-631404b16890--248 | 0062Mu_0000000443 | Menuiserie | 347db150-1122-4b3f-bc21-631404b16890--443
<Unnamed Element> | 4. Etage supérieur | <Unnamed Material> 200 mm | 0062HMu0000000240 | 347db150-1122-4b3f-bc21-631404b16890--240 | 0062Mu_0000000451 | Menuiserie | 347db150-1122-4b3f-bc21-631404b16890--451
<Unnamed Element> | 4. Etage supérieur | <Unnamed Material> 200 mm | 0062HMu0000000232 | 347db150-1122-4b3f-bc21-631404b16890--232 | 0062Mu_0000000245 | Menuiserie | 347db150-1122-4b3f-bc21-631404b16890--245
<Unnamed Element> | 4. Etage supérieur | <Unnamed Material> 200 mm | 0062HMu0000000238 | 347db150-1122-4b3f-bc21-631404b16890--238 | 0062Mu_0000000522 | Menuiserie | 347db150-1122-4b3f-bc21-631404b16890--522
<Unnamed Element> | 4. Etage supérieur | <Unnamed Material> 200 mm | 0062HMu0000000288 | 347db150-1122-4b3f-bc21-631404b16890--288 | 0062Mu_0000000453 | Menuiserie | 347db150-1122-4b3f-bc21-631404b16890--453
<Unnamed Element> | 4. Etage supérieur | <Unnamed Material> 200 mm | 0062HMu0000000281 | 347db150-1122-4b3f-bc21-631404b16890--281 | 0062Mu_0000000286 | Menuiserie | 347db150-1122-4b3f-bc21-631404b16890--286
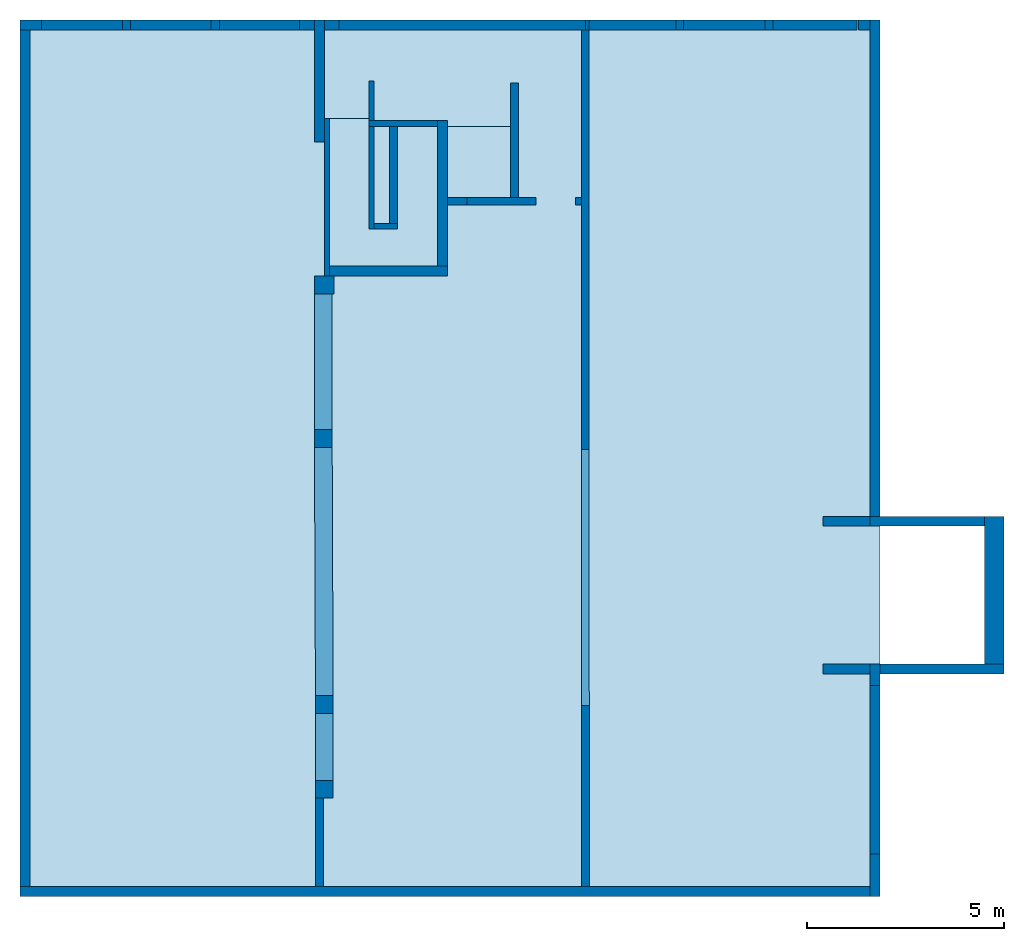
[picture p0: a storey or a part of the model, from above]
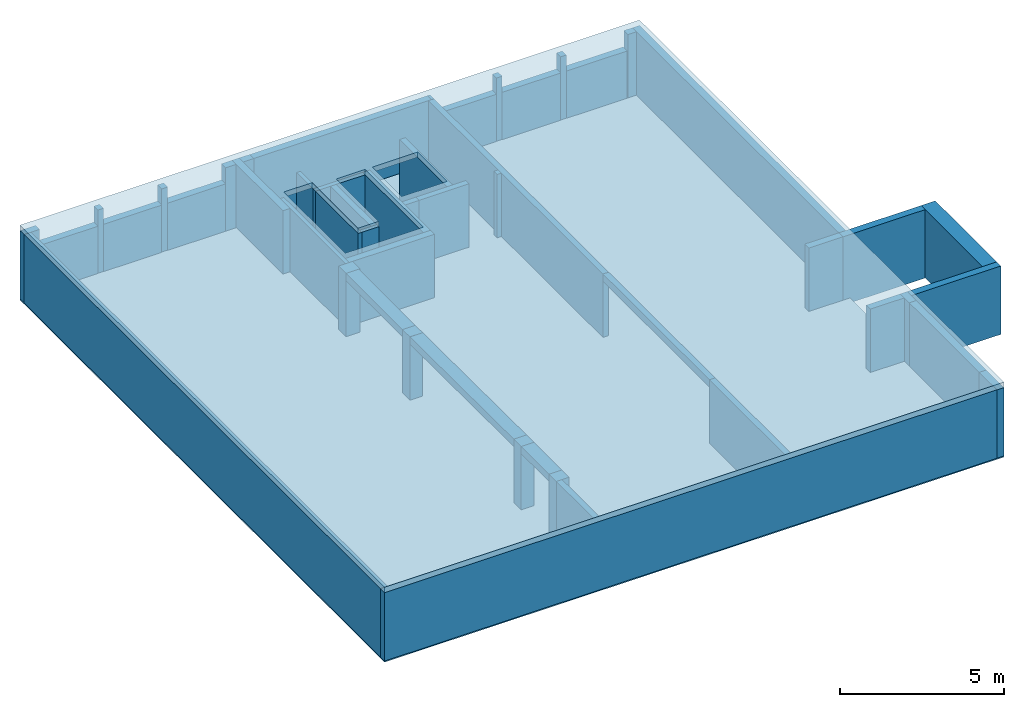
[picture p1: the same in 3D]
Properties of the parts of a building model (IFC2X3), part 2 of 2

# IfcWallStandardCase (211)
Name | In | Material | Id_élt_Allmétré | NOI_UUID | Object Layer Attributes #1, Id_élt_Allmétré | Object Layer Attributes #1, Métier | Object Layer Attributes #1, NOI_UUID
<Unnamed Element> | 4. Etage supérieur | <Unnamed Material> 200 mm | 0062HMu0000000254 | 347db150-1122-4b3f-bc21-631404b16890--254 | 0062Mu_0000000526 | Menuiserie | 347db150-1122-4b3f-bc21-631404b16890--526
<Unnamed Element> | 4. Etage supérieur | <Unnamed Material> 200 mm | 0062HMu0000000236 | 347db150-1122-4b3f-bc21-631404b16890--236 | 0062Mu_0000000382 | Menuiserie | 347db150-1122-4b3f-bc21-631404b16890--382
<Unnamed Element> | 4. Etage supérieur | <Unnamed Material> 101 mm | 0062HMu0000000290 | 347db150-1122-4b3f-bc21-631404b16890--290 | 0062Mu_0000000292 | Menuiserie | 347db150-1122-4b3f-bc21-631404b16890--292
<Unnamed Element> | 5. Etage supérieur | <Unnamed Material> 200 mm | 0071HMu0000001608 | ef38cf39-5122-4ad7-8e20-12f51fd6f56f--1608 | 0071Mu_0000001667 | Menuiserie | ef38cf39-5122-4ad7-8e20-12f51fd6f56f--1667
<Unnamed Element> | 5. Etage supérieur | <Unnamed Material> 200 mm | 0071HMu0000001610 | ef38cf39-5122-4ad7-8e20-12f51fd6f56f--1610 | 0071Mu_0000001622 | Menuiserie | ef38cf39-5122-4ad7-8e20-12f51fd6f56f--1622
<Unnamed Element> | 5. Etage supérieur | <Unnamed Material> 200 mm | 0071HMu0000001612 | ef38cf39-5122-4ad7-8e20-12f51fd6f56f--1612 | 0071Mu_0000001675 | Menuiserie | ef38cf39-5122-4ad7-8e20-12f51fd6f56f--1675
<Unnamed Element> | 5. Etage supérieur | <Unnamed Material> 200 mm | 0071HMu0000001624 | ef38cf39-5122-4ad7-8e20-12f51fd6f56f--1624 | 0071Mu_0000001672 | Menuiserie | ef38cf39-5122-4ad7-8e20-12f51fd6f56f--1672
<Unnamed Element> | 5. Etage supérieur | <Unnamed Material> 200 mm | 0071HMu0000001678 | ef38cf39-5122-4ad7-8e20-12f51fd6f56f--1678 | 0071Mu_0000001690 | Menuiserie | ef38cf39-5122-4ad7-8e20-12f51fd6f56f--1690
<Unnamed Element> | 5. Etage supérieur | <Unnamed Material> 150 mm | 0071HMu0000001687 | ef38cf39-5122-4ad7-8e20-12f51fd6f56f--1687 | 0071Mu_0000001697 | Menuiserie | ef38cf39-5122-4ad7-8e20-12f51fd6f56f--1697
<Unnamed Element> | 5. Etage supérieur | <Unnamed Material> 150 mm | 0071HMu0000001691 | ef38cf39-5122-4ad7-8e20-12f51fd6f56f--1691 | 0071Mu_0000001695 | Menuiserie | ef38cf39-5122-4ad7-8e20-12f51fd6f56f--1695
<Unnamed Element> | 5. Etage supérieur | <Unnamed Material> 200 mm | 0071HMu0000001449 | ef38cf39-5122-4ad7-8e20-12f51fd6f56f--1449 | 0071Mu_0000001475 | Menuiserie | ef38cf39-5122-4ad7-8e20-12f51fd6f56f--1475
<Unnamed Element> | 5. Etage supérieur | <Unnamed Material> 200 mm | 0071HMu0000001429 | ef38cf39-5122-4ad7-8e20-12f51fd6f56f--1429 | 0071Mu_0000001647 | Menuiserie | ef38cf39-5122-4ad7-8e20-12f51fd6f56f--1647
<Unnamed Element> | 5. Etage supérieur | <Unnamed Material> 200 mm | 0071HMu0000001451 | ef38cf39-5122-4ad7-8e20-12f51fd6f56f--1451 | 0071Mu_0000001473 | Menuiserie | ef38cf39-5122-4ad7-8e20-12f51fd6f56f--1473
<Unnamed Element> | 5. Etage supérieur | <Unnamed Material> 200 mm | 0071HMu0000001462 | ef38cf39-5122-4ad7-8e20-12f51fd6f56f--1462 | 0071Mu_0000001489 | Menuiserie | ef38cf39-5122-4ad7-8e20-12f51fd6f56f--1489
<Unnamed Element> | 5. Etage supérieur | <Unnamed Material> 200 mm | 0071HMu0000001491 | ef38cf39-5122-4ad7-8e20-12f51fd6f56f--1491 | 0071Mu_0000001518 | Menuiserie | ef38cf39-5122-4ad7-8e20-12f51fd6f56f--1518
<Unnamed Element> | 5. Etage supérieur | <Unnamed Material> 200 mm | 0071HMu0000001480 | ef38cf39-5122-4ad7-8e20-12f51fd6f56f--1480 | 0071Mu_0000001486 | Menuiserie | ef38cf39-5122-4ad7-8e20-12f51fd6f56f--1486
<Unnamed Element> | 5. Etage supérieur | <Unnamed Material> 200 mm | 0071HMu0000001528 | ef38cf39-5122-4ad7-8e20-12f51fd6f56f--1528 | 0071Mu_0000001539 | Menuiserie | ef38cf39-5122-4ad7-8e20-12f51fd6f56f--1539
<Unnamed Element> | 5. Etage supérieur | <Unnamed Material> 200 mm | 0071HMu0000001343 | ef38cf39-5122-4ad7-8e20-12f51fd6f56f--1343 | 0071Mu_0000001546 | Menuiserie | ef38cf39-5122-4ad7-8e20-12f51fd6f56f--1546
<Unnamed Element> | 5. Etage supérieur | <Unnamed Material> 200 mm | 0071HMu0000001526 | ef38cf39-5122-4ad7-8e20-12f51fd6f56f--1526 | 0071Mu_0000001541 | Menuiserie | ef38cf39-5122-4ad7-8e20-12f51fd6f56f--1541
<Unnamed Element> | 5. Etage supérieur | <Unnamed Material> 200 mm | 0071HMu0000002272 | ef38cf39-5122-4ad7-8e20-12f51fd6f56f--2272 | 0071Mu_0000002273 | Menuiserie | ef38cf39-5122-4ad7-8e20-12f51fd6f56f--2273
<Unnamed Element> | 5. Etage supérieur | <Unnamed Material> 200 mm | 0071HMu0000001364 | ef38cf39-5122-4ad7-8e20-12f51fd6f56f--1364 | 0071Mu_0000001654 | Menuiserie | ef38cf39-5122-4ad7-8e20-12f51fd6f56f--1654
<Unnamed Element> | 5. Etage supérieur | <Unnamed Material> 200 mm | 0071HMu0000001550 | ef38cf39-5122-4ad7-8e20-12f51fd6f56f--1550 | 0071Mu_0000001604 | Menuiserie | ef38cf39-5122-4ad7-8e20-12f51fd6f56f--1604
<Unnamed Element> | 5. Etage supérieur | <Unnamed Material> 200 mm | 0071HMu0000001559 | ef38cf39-5122-4ad7-8e20-12f51fd6f56f--1559 | 0071Mu_0000001587 | Menuiserie | ef38cf39-5122-4ad7-8e20-12f51fd6f56f--1587
<Unnamed Element> | 5. Etage supérieur | <Unnamed Material> 200 mm | 0071HMu0000001575 | ef38cf39-5122-4ad7-8e20-12f51fd6f56f--1575 | 0071Mu_0000001642 | Menuiserie | ef38cf39-5122-4ad7-8e20-12f51fd6f56f--1642
<Unnamed Element> | 5. Etage supérieur | <Unnamed Material> 200 mm | 0071HMu0000001663 | ef38cf39-5122-4ad7-8e20-12f51fd6f56f--1663 | 0071Mu_0000001686 | Menuiserie | ef38cf39-5122-4ad7-8e20-12f51fd6f56f--1686
<Unnamed Element> | 5. Etage supérieur | <Unnamed Material> 200 mm | 0071HMu0000001397 | ef38cf39-5122-4ad7-8e20-12f51fd6f56f--1397 | 0071Mu_0000001639 | Menuiserie | ef38cf39-5122-4ad7-8e20-12f51fd6f56f--1639
<Unnamed Element> | 5. Etage supérieur | <Unnamed Material> 101 mm | 0071HMu0000001681 | ef38cf39-5122-4ad7-8e20-12f51fd6f56f--1681 | 0071Mu_0000001684 | Menuiserie | ef38cf39-5122-4ad7-8e20-12f51fd6f56f--1684
<Unnamed Element> | 5. Etage supérieur | <Unnamed Material> 150 mm | 0071HMu0000001660 | ef38cf39-5122-4ad7-8e20-12f51fd6f56f--1660 | 0071Mu_0000001669 | Menuiserie | ef38cf39-5122-4ad7-8e20-12f51fd6f56f--1669
<Unnamed Element> | 6. Etage supérieur | <Unnamed Material> 200 mm | 0082HMu0000000022 | 5473e48a-e790-4312-ac25-e6982c2e7877--22 | 0082Mu_0000000023 | Béton et béton armé | 5473e48a-e790-4312-ac25-e6982c2e7877--23
<Unnamed Element> | 6. Etage supérieur | <Unnamed Material> 200 mm | 0082HMu0000000047 | 5473e48a-e790-4312-ac25-e6982c2e7877--47 | 0082Mu_0000000048 | Béton et béton armé | 5473e48a-e790-4312-ac25-e6982c2e7877--48
<Unnamed Element> | 6. Etage supérieur | <Unnamed Material> 200 mm | 0082HMu0000000082 | 5473e48a-e790-4312-ac25-e6982c2e7877--82 | 0082Mu_0000000083 | Béton et béton armé | 5473e48a-e790-4312-ac25-e6982c2e7877--83
<Unnamed Element> | 6. Etage supérieur | <Unnamed Material> 200 mm | 0082HMu0000000092 | 5473e48a-e790-4312-ac25-e6982c2e7877--92 | 0082Mu_0000000093 | Béton et béton armé | 5473e48a-e790-4312-ac25-e6982c2e7877--93
<Unnamed Element> | 6. Etage supérieur | <Unnamed Material> 200 mm | 0082HMu0000000100 | 5473e48a-e790-4312-ac25-e6982c2e7877--100 | 0082Mu_0000000101 | Béton et béton armé | 5473e48a-e790-4312-ac25-e6982c2e7877--101
<Unnamed Element> | 6. Etage supérieur | <Unnamed Material> 200 mm | 0082HMu0000000110 | 5473e48a-e790-4312-ac25-e6982c2e7877--110 | 0082Mu_0000000111 | Béton et béton armé | 5473e48a-e790-4312-ac25-e6982c2e7877--111
<Unnamed Element> | 6. Etage supérieur | <Unnamed Material> 200 mm | 0082HMu0000000182 | 5473e48a-e790-4312-ac25-e6982c2e7877--182 | 0082Mu_0000000183 | Béton et béton armé | 5473e48a-e790-4312-ac25-e6982c2e7877--183
<Unnamed Element> | 6. Etage supérieur | <Unnamed Material> 200 mm | 0082HMu0000000193 | 5473e48a-e790-4312-ac25-e6982c2e7877--193 | 0082Mu_0000000194 | Béton et béton armé | 5473e48a-e790-4312-ac25-e6982c2e7877--194
<Unnamed Element> | 6. Etage supérieur | <Unnamed Material> 150 mm | 0082HMu0000000243 | 5473e48a-e790-4312-ac25-e6982c2e7877--243 | 0082Mu_0000000244 | Béton et béton armé | 5473e48a-e790-4312-ac25-e6982c2e7877--244
<Unnamed Element> | 6. Etage supérieur | <Unnamed Material> 150 mm | 0082HMu0000000254 | 5473e48a-e790-4312-ac25-e6982c2e7877--254 | 0082Mu_0000000255 | Béton et béton armé | 5473e48a-e790-4312-ac25-e6982c2e7877--255
<Unnamed Element> | 6. Etage supérieur | <Unnamed Material> 150 mm | 0082HMu0000000264 | 5473e48a-e790-4312-ac25-e6982c2e7877--264 | 0082Mu_0000000265 | Béton et béton armé | 5473e48a-e790-4312-ac25-e6982c2e7877--265
<Unnamed Element> | 6. Etage supérieur | <Unnamed Material> 200 mm | 0082HMu0000000206 | 5473e48a-e790-4312-ac25-e6982c2e7877--206 | 0082Mu_0000000207 | Béton et béton armé | 5473e48a-e790-4312-ac25-e6982c2e7877--207
<Unnamed Element> | 6. Etage supérieur | <Unnamed Material> 200 mm | 0082HMu0000000473 | 5473e48a-e790-4312-ac25-e6982c2e7877--473 | 0082Mu_0000000474 | Béton et béton armé | 5473e48a-e790-4312-ac25-e6982c2e7877--474
<Unnamed Element> | 6. Etage supérieur | <Unnamed Material> 200 mm | 0082HMu0000000492 | 5473e48a-e790-4312-ac25-e6982c2e7877--492 | 0082Mu_0000000494 | Béton et béton armé | 5473e48a-e790-4312-ac25-e6982c2e7877--494
<Unnamed Element> | 6. Etage supérieur | <Unnamed Material> 100 mm | 0082HMu0000000530 | 5473e48a-e790-4312-ac25-e6982c2e7877--530 | 0082Mu_0000000531 | Béton et béton armé | 5473e48a-e790-4312-ac25-e6982c2e7877--531
<Unnamed Element> | 6. Etage supérieur | <Unnamed Material> 200 mm | 0082HMu0000000374 | 5473e48a-e790-4312-ac25-e6982c2e7877--374 | 0082Mu_0000000376 | Béton et béton armé | 5473e48a-e790-4312-ac25-e6982c2e7877--376
<Unnamed Element> | 6. Etage supérieur | <Unnamed Material> 200 mm | 0082HMu0000000878 | 5473e48a-e790-4312-ac25-e6982c2e7877--878 | 0082Mu_0000000883 | Béton et béton armé | 5473e48a-e790-4312-ac25-e6982c2e7877--883
<Unnamed Element> | 6. Etage supérieur | <Unnamed Material> 200 mm | 0082HMu0000000120 | 5473e48a-e790-4312-ac25-e6982c2e7877--120 | 0082Mu_0000000121 | Béton et béton armé | 5473e48a-e790-4312-ac25-e6982c2e7877--121
<Unnamed Element> | 6. Etage supérieur | <Unnamed Material> 200 mm | 0082HMu0000000072 | 5473e48a-e790-4312-ac25-e6982c2e7877--72 | 0082Mu_0000000073 | Béton et béton armé | 5473e48a-e790-4312-ac25-e6982c2e7877--73
<Unnamed Element> | 7. Etage supérieur | <Unnamed Material> 0.10944 mm | 0092HMu0000000204 | 1387ea74-cd35-46e1-bbd3-7339ea09bb96--204 | 0092Mu_0000000205 | Béton et béton armé | 1387ea74-cd35-46e1-bbd3-7339ea09bb96--205
<Unnamed Element> | 7. Etage supérieur | <Unnamed Material> 150 mm | 0092HMu0000000242 | 1387ea74-cd35-46e1-bbd3-7339ea09bb96--242 | 0092Mu_0000000243 | Béton et béton armé | 1387ea74-cd35-46e1-bbd3-7339ea09bb96--243
<Unnamed Element> | 7. Etage supérieur | <Unnamed Material> 150 mm | 0092HMu0000000253 | 1387ea74-cd35-46e1-bbd3-7339ea09bb96--253 | 0092Mu_0000000254 | Béton et béton armé | 1387ea74-cd35-46e1-bbd3-7339ea09bb96--254
<Unnamed Element> | 7. Etage supérieur | <Unnamed Material> 200 mm | 0092HMu0000000290 | 1387ea74-cd35-46e1-bbd3-7339ea09bb96--290 | 0092Mu_0000000291 | Béton et béton armé | 1387ea74-cd35-46e1-bbd3-7339ea09bb96--291
<Unnamed Element> | 7. Etage supérieur | <Unnamed Material> 200 mm | 0092HMu0000000305 | 1387ea74-cd35-46e1-bbd3-7339ea09bb96--305 | 0092Mu_0000000306 | Béton et béton armé | 1387ea74-cd35-46e1-bbd3-7339ea09bb96--306
<Unnamed Element> | 7. Etage supérieur | <Unnamed Material> 200 mm | 0092HMu0000000316 | 1387ea74-cd35-46e1-bbd3-7339ea09bb96--316 | 0092Mu_0000000317 | Béton et béton armé | 1387ea74-cd35-46e1-bbd3-7339ea09bb96--317
<Unnamed Element> | 7. Etage supérieur | <Unnamed Material> 100 mm | 0092HMu0000000339 | 1387ea74-cd35-46e1-bbd3-7339ea09bb96--339 | 0092Mu_0000000340 | Béton et béton armé | 1387ea74-cd35-46e1-bbd3-7339ea09bb96--340
<Unnamed Element> | 7. Etage supérieur | <Unnamed Material> 100 mm | 0092HMu0000000350 | 1387ea74-cd35-46e1-bbd3-7339ea09bb96--350 | 0092Mu_0000000351 | Béton et béton armé | 1387ea74-cd35-46e1-bbd3-7339ea09bb96--351
<Unnamed Element> | 7. Etage supérieur | <Unnamed Material> 200 mm | 0092HMu0000000422 | 1387ea74-cd35-46e1-bbd3-7339ea09bb96--422 | 0092Mu_0000000423 | Béton et béton armé | 1387ea74-cd35-46e1-bbd3-7339ea09bb96--423
<Unnamed Element> | 7. Etage supérieur | <Unnamed Material> 200 mm | 0092HMu0000000485 | 1387ea74-cd35-46e1-bbd3-7339ea09bb96--485 | 0092Mu_0000000486 | Béton et béton armé | 1387ea74-cd35-46e1-bbd3-7339ea09bb96--486
<Unnamed Element> | 7. Etage supérieur | <Unnamed Material> 200 mm | 0092HMu0000000527 | 1387ea74-cd35-46e1-bbd3-7339ea09bb96--527 | 0092Mu_0000000528 | Béton et béton armé | 1387ea74-cd35-46e1-bbd3-7339ea09bb96--528
<Unnamed Element> | 7. Etage supérieur | <Unnamed Material> 200 mm | 0092HMu0000000545 | 1387ea74-cd35-46e1-bbd3-7339ea09bb96--545 | 0092Mu_0000000546 | Béton et béton armé | 1387ea74-cd35-46e1-bbd3-7339ea09bb96--546
<Unnamed Element> | 7. Etage supérieur | <Unnamed Material> 200 mm | 0092HMu0000000614 | 1387ea74-cd35-46e1-bbd3-7339ea09bb96--614 | 0092Mu_0000000615 | Béton et béton armé | 1387ea74-cd35-46e1-bbd3-7339ea09bb96--615
